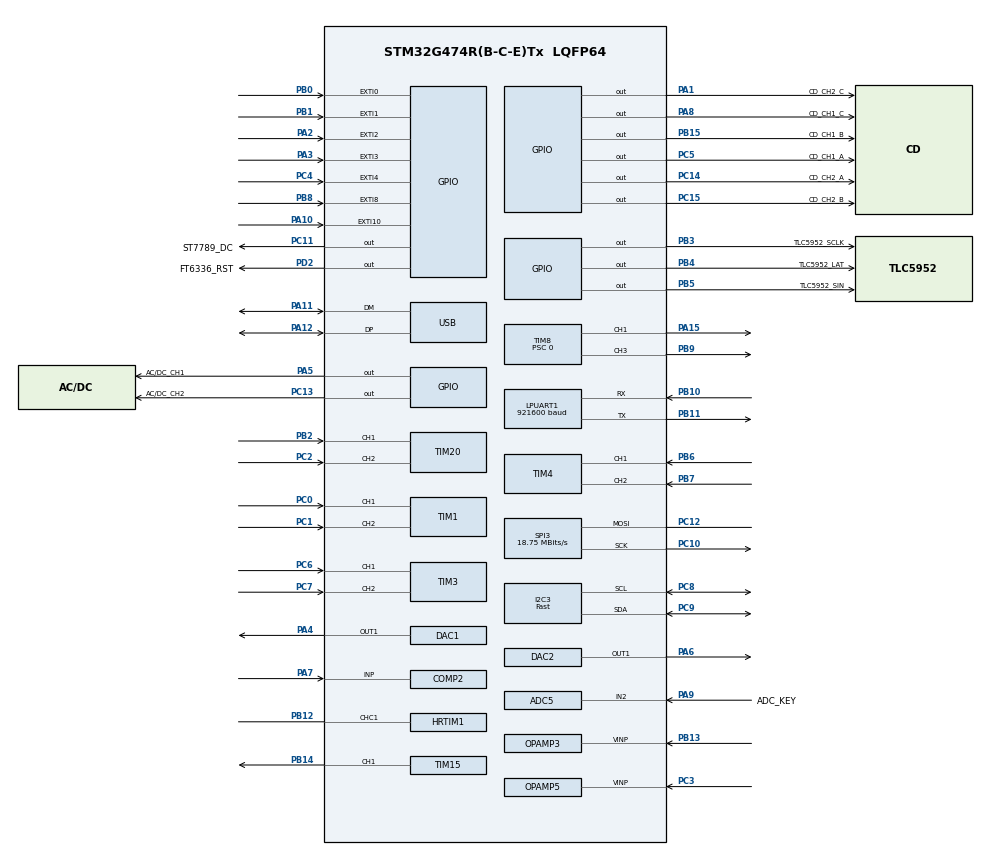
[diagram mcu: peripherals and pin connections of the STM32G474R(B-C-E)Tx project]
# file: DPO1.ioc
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ADC2.Channel-0\#ChannelRegularConversion=ADC_CHANNEL_4
ADC2.ClockPrescaler=ADC_CLOCK_ASYNC_DIV1
ADC2.ContinuousConvMode=DISABLE
ADC2.DMAContinuousRequests=ENABLE
ADC2.ExternalTrigConv=ADC_EXTERNALTRIG_T6_TRGO
ADC2.NbrOfConversionFlag=1
ADC2.OffsetNumber-0\#ChannelRegularConversion=ADC_OFFSET_NONE
ADC2.Overrun=ADC_OVR_DATA_OVERWRITTEN
ADC2.Rank-0\#ChannelRegularConversion=1
ADC2.SamplingTime-0\#ChannelRegularConversion=ADC_SAMPLETIME_2CYCLES_5
ADC3.Channel-0\#ChannelRegularConversion=ADC_CHANNEL_5
ADC3.ClockPrescaler=ADC_CLOCK_ASYNC_DIV1
ADC3.ContinuousConvMode=DISABLE
ADC3.DMAContinuousRequests=ENABLE
ADC3.ExternalTrigConv=ADC_EXTERNALTRIG_T6_TRGO
ADC3.NbrOfConversionFlag=1
ADC3.OffsetNumber-0\#ChannelRegularConversion=ADC_OFFSET_NONE
ADC3.Overrun=ADC_OVR_DATA_OVERWRITTEN
ADC3.Rank-0\#ChannelRegularConversion=1
ADC3.SamplingTime-0\#ChannelRegularConversion=ADC_SAMPLETIME_2CYCLES_5
ADC3.master=1
ADC5.AWD1FilteringConfig=ADC_AWD_FILTERING_NONE
ADC5.AWD1HighThreshold=4095
ADC5.AWD1ITMode=ENABLE
ADC5.AWD1LowThreshold=3500
ADC5.Channel-0\#ChannelRegularConversion=ADC_CHANNEL_2
ADC5.Channel-1\#ChannelRegularConversion=ADC_CHANNEL_TEMPSENSOR_ADC5
ADC5.Channel-2\#ChannelRegularConversion=ADC_CHANNEL_VBAT
ADC5.Channel-3\#ChannelRegularConversion=ADC_CHANNEL_VREFINT
ADC5.Channel-4\#ChannelRegularConversion=ADC_CHANNEL_VOPAMP5
ADC5.ClockPrescaler=ADC_CLOCK_ASYNC_DIV1
ADC5.ContinuousConvMode=ENABLE
ADC5.DMAContinuousRequests=ENABLE
ADC5.DiscontinuousConvMode=DISABLE
ADC5.EOCSelection=ADC_EOC_SEQ_CONV
ADC5.EnableAnalogWatchDog1=true
ADC5.ExternalTrigConv=ADC_EXTERNALTRIG_T7_TRGO
ADC5.NbrOfConversion=5
ADC5.NbrOfConversionFlag=1
ADC5.OffsetNumber-0\#ChannelRegularConversion=ADC_OFFSET_NONE
ADC5.OffsetNumber-1\#ChannelRegularConversion=ADC_OFFSET_NONE
ADC5.OffsetNumber-2\#ChannelRegularConversion=ADC_OFFSET_NONE
ADC5.OffsetNumber-3\#ChannelRegularConversion=ADC_OFFSET_NONE
ADC5.OffsetNumber-4\#ChannelRegularConversion=ADC_OFFSET_NONE
ADC5.Overrun=ADC_OVR_DATA_OVERWRITTEN
ADC5.Rank-0\#ChannelRegularConversion=1
ADC5.Rank-1\#ChannelRegularConversion=2
ADC5.Rank-2\#ChannelRegularConversion=3
ADC5.Rank-3\#ChannelRegularConversion=4
ADC5.Rank-4\#ChannelRegularConversion=5
ADC5.Resolution=ADC_RESOLUTION_12B
ADC5.SamplingTime-0\#ChannelRegularConversion=ADC_SAMPLETIME_640CYCLES_5
ADC5.SamplingTime-1\#ChannelRegularConversion=ADC_SAMPLETIME_640CYCLES_5
ADC5.SamplingTime-2\#ChannelRegularConversion=ADC_SAMPLETIME_640CYCLES_5
ADC5.SamplingTime-3\#ChannelRegularConversion=ADC_SAMPLETIME_640CYCLES_5
ADC5.SamplingTime-4\#ChannelRegularConversion=ADC_SAMPLETIME_640CYCLES_5
ADC5.WatchdogChannel=ADC_CHANNEL_2
ADC5.WatchdogMode=ADC_ANALOGWATCHDOG_SINGLE_REG
DAC1.DAC_Channel-DAC_OUT2_Int=DAC_CHANNEL_2
DAC1.DAC_Trigger2_OUT1-DAC_OUT1_ExtAndInt=DAC_TRIGGER_NONE
DAC1.DAC_Trigger_OUT1-DAC_OUT1_ExtAndInt=DAC_TRIGGER_SOFTWARE
DAC1.WaveGeneration_OUT1-DAC_OUT1_ExtAndInt=DISABLE
DAC2.DAC_Trigger_OUT1-DAC_OUT1_ExtAndInt=DAC_TRIGGER_SOFTWARE
DAC4.DAC_Trigger_OUT1-DAC_OUT1_Int=DAC_TRIGGER_SOFTWARE
Dma.ADC2.4.Direction=DMA_PERIPH_TO_MEMORY
Dma.ADC2.4.EventEnable=DISABLE
Dma.ADC2.4.Instance=DMA1_Channel5
Dma.ADC2.4.MemDataAlignment=DMA_MDATAALIGN_WORD
Dma.ADC2.4.MemInc=DMA_MINC_ENABLE
Dma.ADC2.4.Mode=DMA_CIRCULAR
Dma.ADC2.4.PeriphDataAlignment=DMA_PDATAALIGN_WORD
Dma.ADC2.4.PeriphInc=DMA_PINC_DISABLE
Dma.ADC2.4.Polarity=HAL_DMAMUX_REQ_GEN_RISING
Dma.ADC2.4.Priority=DMA_PRIORITY_LOW
Dma.ADC2.4.RequestNumber=1
Dma.ADC2.4.SignalID=NONE
Dma.ADC2.4.SyncEnable=DISABLE
Dma.ADC2.4.SyncPolarity=HAL_DMAMUX_SYNC_NO_EVENT
Dma.ADC2.4.SyncRequestNumber=1
Dma.ADC2.4.SyncSignalID=NONE
Dma.ADC3.5.Direction=DMA_PERIPH_TO_MEMORY
Dma.ADC3.5.EventEnable=DISABLE
Dma.ADC3.5.Instance=DMA1_Channel6
Dma.ADC3.5.MemDataAlignment=DMA_MDATAALIGN_WORD
Dma.ADC3.5.MemInc=DMA_MINC_ENABLE
Dma.ADC3.5.Mode=DMA_CIRCULAR
Dma.ADC3.5.PeriphDataAlignment=DMA_PDATAALIGN_WORD
Dma.ADC3.5.PeriphInc=DMA_PINC_DISABLE
Dma.ADC3.5.Polarity=HAL_DMAMUX_REQ_GEN_RISING
Dma.ADC3.5.Priority=DMA_PRIORITY_LOW
Dma.ADC3.5.RequestNumber=1
Dma.ADC3.5.SignalID=NONE
Dma.ADC3.5.SyncEnable=DISABLE
Dma.ADC3.5.SyncPolarity=HAL_DMAMUX_SYNC_NO_EVENT
Dma.ADC3.5.SyncRequestNumber=1
Dma.ADC3.5.SyncSignalID=NONE
Dma.ADC5.3.Direction=DMA_PERIPH_TO_MEMORY
Dma.ADC5.3.EventEnable=DISABLE
Dma.ADC5.3.Instance=DMA1_Channel4
Dma.ADC5.3.MemDataAlignment=DMA_MDATAALIGN_WORD
Dma.ADC5.3.MemInc=DMA_MINC_ENABLE
Dma.ADC5.3.Mode=DMA_CIRCULAR
Dma.ADC5.3.PeriphDataAlignment=DMA_PDATAALIGN_WORD
Dma.ADC5.3.PeriphInc=DMA_PINC_DISABLE
Dma.ADC5.3.Polarity=HAL_DMAMUX_REQ_GEN_RISING
Dma.ADC5.3.Priority=DMA_PRIORITY_LOW
Dma.ADC5.3.RequestNumber=1
Dma.ADC5.3.SignalID=NONE
Dma.ADC5.3.SyncEnable=DISABLE
Dma.ADC5.3.SyncPolarity=HAL_DMAMUX_SYNC_NO_EVENT
Dma.ADC5.3.SyncRequestNumber=1
Dma.ADC5.3.SyncSignalID=NONE
Dma.Request0=TIM8_CH3
Dma.Request1=TIM15_CH1
Dma.Request2=SPI3_TX
Dma.Request3=ADC5
Dma.Request4=ADC2
Dma.Request5=ADC3
Dma.SPI3_TX.2.Direction=DMA_MEMORY_TO_PERIPH
Dma.SPI3_TX.2.EventEnable=DISABLE
Dma.SPI3_TX.2.Instance=DMA1_Channel3
Dma.SPI3_TX.2.MemDataAlignment=DMA_MDATAALIGN_BYTE
Dma.SPI3_TX.2.MemInc=DMA_MINC_ENABLE
Dma.SPI3_TX.2.Mode=DMA_NORMAL
Dma.SPI3_TX.2.PeriphDataAlignment=DMA_PDATAALIGN_BYTE
Dma.SPI3_TX.2.PeriphInc=DMA_PINC_DISABLE
Dma.SPI3_TX.2.Polarity=HAL_DMAMUX_REQ_GEN_RISING
Dma.SPI3_TX.2.Priority=DMA_PRIORITY_LOW
Dma.SPI3_TX.2.RequestNumber=1
Dma.SPI3_TX.2.SignalID=NONE
Dma.SPI3_TX.2.SyncEnable=DISABLE
Dma.SPI3_TX.2.SyncPolarity=HAL_DMAMUX_SYNC_NO_EVENT
Dma.SPI3_TX.2.SyncRequestNumber=1
Dma.SPI3_TX.2.SyncSignalID=NONE
Dma.TIM15_CH1.1.Direction=DMA_MEMORY_TO_PERIPH
Dma.TIM15_CH1.1.EventEnable=DISABLE
Dma.TIM15_CH1.1.Instance=DMA1_Channel2
Dma.TIM15_CH1.1.MemDataAlignment=DMA_MDATAALIGN_HALFWORD
Dma.TIM15_CH1.1.MemInc=DMA_MINC_ENABLE
Dma.TIM15_CH1.1.Mode=DMA_NORMAL
Dma.TIM15_CH1.1.PeriphDataAlignment=DMA_PDATAALIGN_HALFWORD
Dma.TIM15_CH1.1.PeriphInc=DMA_PINC_DISABLE
Dma.TIM15_CH1.1.Polarity=HAL_DMAMUX_REQ_GEN_RISING
Dma.TIM15_CH1.1.Priority=DMA_PRIORITY_LOW
Dma.TIM15_CH1.1.RequestNumber=1
Dma.TIM15_CH1.1.SignalID=NONE
Dma.TIM15_CH1.1.SyncEnable=DISABLE
Dma.TIM15_CH1.1.SyncPolarity=HAL_DMAMUX_SYNC_NO_EVENT
Dma.TIM15_CH1.1.SyncRequestNumber=1
Dma.TIM15_CH1.1.SyncSignalID=NONE
Dma.TIM8_CH3.0.Direction=DMA_MEMORY_TO_PERIPH
Dma.TIM8_CH3.0.EventEnable=DISABLE
Dma.TIM8_CH3.0.Instance=DMA1_Channel1
Dma.TIM8_CH3.0.MemDataAlignment=DMA_MDATAALIGN_HALFWORD
Dma.TIM8_CH3.0.MemInc=DMA_MINC_ENABLE
Dma.TIM8_CH3.0.Mode=DMA_NORMAL
Dma.TIM8_CH3.0.PeriphDataAlignment=DMA_PDATAALIGN_HALFWORD
Dma.TIM8_CH3.0.PeriphInc=DMA_PINC_DISABLE
Dma.TIM8_CH3.0.Polarity=HAL_DMAMUX_REQ_GEN_RISING
Dma.TIM8_CH3.0.Priority=DMA_PRIORITY_LOW
Dma.TIM8_CH3.0.RequestNumber=1
Dma.TIM8_CH3.0.SignalID=NONE
Dma.TIM8_CH3.0.SyncEnable=DISABLE
Dma.TIM8_CH3.0.SyncPolarity=HAL_DMAMUX_SYNC_NO_EVENT
Dma.TIM8_CH3.0.SyncRequestNumber=1
Dma.TIM8_CH3.0.SyncSignalID=NONE
HRTIM1.CompareUnit1-Output_TC1=HRTIM_COMPAREUNIT_1
HRTIM1.CompareValue1-Output_TC1=48
HRTIM1.Configuration_TC=Waveform
HRTIM1.NumberResetSource1-Output_TC1=1
HRTIM1.NumberSetSource1-Output_TC1=1
HRTIM1.Periode_TC=96
HRTIM1.ResetOutput1_Source1-Output_TC1=HRTIM_OUTPUTRESET_TIMCMP1
HRTIM1.SetOutput1_Source1-Output_TC1=HRTIM_OUTPUTSET_TIMPER
I2C3.I2C_Speed_Mode=I2C_Fast
I2C3.Timing=0x10E32879
LPUART1.BaudRate=921600
Mcu.Family=STM32G4
Mcu.Name=STM32G474R(B-C-E)Tx
Mcu.Package=LQFP64
NVIC.ADC5_IRQn=true\:0\:0\:false\:false\:true\:true\:true\:true
NVIC.DMA1_Channel1_IRQn=true\:0\:0\:false\:false\:true\:false\:true\:true
NVIC.DMA1_Channel2_IRQn=true\:0\:0\:false\:false\:true\:false\:true\:true
NVIC.DMA1_Channel3_IRQn=true\:0\:0\:false\:false\:true\:false\:true\:true
NVIC.DMA1_Channel4_IRQn=true\:0\:0\:false\:false\:true\:false\:true\:true
NVIC.DMA1_Channel5_IRQn=true\:0\:0\:false\:false\:true\:false\:true\:true
NVIC.DMA1_Channel6_IRQn=true\:0\:0\:false\:false\:true\:false\:true\:true
NVIC.EXTI0_IRQn=true\:0\:0\:false\:false\:true\:true\:true\:true
NVIC.EXTI15_10_IRQn=true\:0\:0\:false\:false\:true\:true\:true\:true
NVIC.EXTI1_IRQn=true\:0\:0\:false\:false\:true\:true\:true\:true
NVIC.EXTI2_IRQn=true\:0\:0\:false\:false\:true\:true\:true\:true
NVIC.EXTI3_IRQn=true\:0\:0\:false\:false\:true\:true\:true\:true
NVIC.EXTI4_IRQn=true\:0\:0\:false\:false\:true\:true\:true\:true
NVIC.EXTI9_5_IRQn=true\:0\:0\:false\:false\:true\:true\:true\:true
NVIC.PriorityGroup=NVIC_PRIORITYGROUP_4
NVIC.USB_LP_IRQn=true\:0\:0\:false\:false\:true\:false\:true\:true
PA0.Signal=S_TIM2_ETR
PA1.GPIO_Label=CD_CH2_C
PA1.Signal=GPIO_Output
PA10.Signal=GPXTI10
PA11.Mode=Device
PA11.Signal=USB_DM
PA12.Mode=Device
PA12.Signal=USB_DP
PA13.Mode=Serial_Wire
PA13.Signal=SYS_JTMS-SWDIO
PA14.Mode=Serial_Wire
PA14.Signal=SYS_JTCK-SWCLK
PA15.GPIO_ModeDefaultPP=GPIO_MODE_AF_PP
PA15.GPIO_PuPd=GPIO_PULLDOWN
PA15.GPIO_Speed=GPIO_SPEED_FREQ_VERY_HIGH
PA15.Signal=S_TIM8_CH1
PA2.Signal=GPXTI2
PA3.Signal=GPXTI3
PA4.Signal=COMP_DAC11_group
PA5.GPIO_Label=AC/DC_CH1
PA5.Signal=GPIO_Output
PA6.Signal=COMP_DAC21_group
PA7.Signal=SharedAnalog_PA7
PA8.GPIO_Label=CD_CH1_C
PA8.Signal=GPIO_Output
PA9.GPIO_Label=ADC_KEY
PA9.Mode=IN2-Single-Ended
PA9.Signal=ADC5_IN2
PB0.Signal=GPXTI0
PB1.Signal=GPXTI1
PB10.Mode=Asynchronous
PB10.Signal=LPUART1_RX
PB11.Mode=Asynchronous
PB11.Signal=LPUART1_TX
PB12.Mode=Output_TC1
PB12.Signal=HRTIM1_CHC1
PB13.Signal=SharedAnalog_PB13
PB14.GPIO_ModeDefaultPP=GPIO_MODE_AF_PP
PB14.GPIO_PuPd=GPIO_PULLUP
PB14.GPIO_Speed=GPIO_SPEED_FREQ_VERY_HIGH
PB14.Signal=S_TIM15_CH1
PB15.GPIO_Label=CD_CH1_B
PB15.Signal=GPIO_Output
PB2.GPIO_PuPd=GPIO_PULLUP
PB2.GPIO_Speed=GPIO_SPEED_FREQ_VERY_HIGH
PB2.Signal=S_TIM20_CH1
PB3.GPIO_Label=TLC5952_SCLK
PB3.Signal=GPIO_Output
PB4.GPIO_Label=TLC5952_LAT
PB4.Signal=GPIO_Output
PB5.GPIO_Label=TLC5952_SIN
PB5.Signal=GPIO_Output
PB6.GPIO_PuPd=GPIO_PULLUP
PB6.GPIO_Speed=GPIO_SPEED_FREQ_VERY_HIGH
PB6.Signal=S_TIM4_CH1
PB7.GPIO_PuPd=GPIO_PULLUP
PB7.GPIO_Speed=GPIO_SPEED_FREQ_VERY_HIGH
PB7.Signal=S_TIM4_CH2
PB8-BOOT0.Signal=GPXTI8
PB9.GPIO_ModeDefaultPP=GPIO_MODE_AF_PP
PB9.GPIO_PuPd=GPIO_NOPULL
PB9.GPIO_Speed=GPIO_SPEED_FREQ_VERY_HIGH
PB9.Signal=S_TIM8_CH3
PC0.GPIO_PuPd=GPIO_PULLUP
PC0.GPIO_Speed=GPIO_SPEED_FREQ_VERY_HIGH
PC0.Signal=S_TIM1_CH1
PC1.GPIO_PuPd=GPIO_PULLUP
PC1.GPIO_Speed=GPIO_SPEED_FREQ_VERY_HIGH
PC1.Signal=S_TIM1_CH2
PC10.GPIO_Mode=GPIO_MODE_AF_PP
PC10.GPIO_PuPd=GPIO_NOPULL
PC10.GPIO_Speed=GPIO_SPEED_FREQ_VERY_HIGH
PC10.Mode=Simplex_Bidirectional_Master
PC10.Signal=SPI3_SCK
PC11.GPIO_Label=ST7789_DC
PC11.Signal=GPIO_Output
PC12.GPIO_Mode=GPIO_MODE_AF_PP
PC12.GPIO_PuPd=GPIO_NOPULL
PC12.GPIO_Speed=GPIO_SPEED_FREQ_VERY_HIGH
PC12.Mode=Simplex_Bidirectional_Master
PC12.Signal=SPI3_MOSI
PC13.GPIO_Label=AC/DC_CH2
PC13.Signal=GPIO_Output
PC14-OSC32_IN.GPIO_Label=CD_CH2_A
PC14-OSC32_IN.Signal=GPIO_Output
PC15-OSC32_OUT.GPIO_Label=CD_CH2_B
PC15-OSC32_OUT.Signal=GPIO_Output
PC2.GPIO_PuPd=GPIO_PULLUP
PC2.GPIO_Speed=GPIO_SPEED_FREQ_VERY_HIGH
PC2.Signal=S_TIM20_CH2
PC3.Mode=Follower_Internally_Connected
PC3.Signal=OPAMP5_VINP
PC4.Signal=GPXTI4
PC5.GPIO_Label=CD_CH1_A
PC5.Signal=GPIO_Output
PC6.GPIO_PuPd=GPIO_PULLUP
PC6.GPIO_Speed=GPIO_SPEED_FREQ_VERY_HIGH
PC6.Signal=S_TIM3_CH1
PC7.GPIO_PuPd=GPIO_PULLUP
PC7.GPIO_Speed=GPIO_SPEED_FREQ_VERY_HIGH
PC7.Signal=S_TIM3_CH2
PC8.Mode=I2C
PC8.Signal=I2C3_SCL
PC9.Mode=I2C
PC9.Signal=I2C3_SDA
PD2.GPIO_Label=FT6336_RST
PD2.Signal=GPIO_Output
PF0-OSC_IN.Mode=HSE-External-Oscillator
PF0-OSC_IN.Signal=RCC_OSC_IN
PF1-OSC_OUT.Mode=HSE-External-Oscillator
PF1-OSC_OUT.Signal=RCC_OSC_OUT
ProjectManager.HeapSize=0x200
ProjectManager.StackSize=0x400
ProjectManager.TargetToolchain=STM32CubeIDE
RCC.ADC12Freq_Value=150000000
RCC.ADC345CLockSelection=RCC_ADC345CLKSOURCE_PLL
RCC.ADC345Freq_Value=50000000
RCC.AHBFreq_Value=150000000
RCC.APB1Freq_Value=150000000
RCC.APB1TimFreq_Value=150000000
RCC.APB2Freq_Value=150000000
RCC.APB2TimFreq_Value=150000000
RCC.CK48CLockSelection=RCC_USBCLKSOURCE_HSI48
RCC.CortexFreq_Value=150000000
RCC.EXTERNAL_CLOCK_VALUE=12288000
RCC.EnbaleCSS=true
RCC.HCLKFreq_Value=150000000
RCC.HSE_VALUE=8000000
RCC.HSI48_VALUE=48000000
RCC.HSI_VALUE=16000000
RCC.LSE_VALUE=32768
RCC.PLLM=RCC_PLLM_DIV2
RCC.PLLN=75
RCC.PLLP=RCC_PLLP_DIV6
RCC.PLLSourceVirtual=RCC_PLLSOURCE_HSE
RCC.SYSCLKFreq_VALUE=150000000
RCC.SYSCLKSource=RCC_SYSCLKSOURCE_PLLCLK
RCC.USBFreq_Value=48000000
RCC.VCOOutputFreq_Value=300000000
SH.COMP_DAC11_group.0=DAC1_OUT1,DAC_OUT1_ExtAndInt
SH.COMP_DAC21_group.0=DAC2_OUT1,DAC_OUT1_ExtAndInt
SH.S_TIM15_CH1.0=TIM15_CH1,PWM Generation1 CH1
SH.S_TIM1_CH1.0=TIM1_CH1,Encoder_Interface
SH.S_TIM1_CH2.0=TIM1_CH2,Encoder_Interface
SH.S_TIM20_CH1.0=TIM20_CH1,Encoder_Interface
SH.S_TIM20_CH2.0=TIM20_CH2,Encoder_Interface
SH.S_TIM2_ETR.0=TIM2_ETR
SH.S_TIM3_CH1.0=TIM3_CH1,Encoder_Interface
SH.S_TIM3_CH2.0=TIM3_CH2,Encoder_Interface
SH.S_TIM4_CH1.0=TIM4_CH1,Encoder_Interface
SH.S_TIM4_CH2.0=TIM4_CH2,Encoder_Interface
SH.S_TIM8_CH1.0=TIM8_CH1,PWM Generation1 CH1
SH.S_TIM8_CH3.0=TIM8_CH3,PWM Generation3 CH3
SH.SharedAnalog_PA7.0=COMP2_INP,INP
SH.SharedAnalog_PA7.1=OPAMP1_VINP,PGA_Internally_Connected
SH.SharedAnalog_PA7.2=OPAMP2_VINP,Follower_Internally_Connected
SH.SharedAnalog_PA7.3=ADC2_IN4,IN4-Single-Ended
SH.SharedAnalog_PB13.0=OPAMP3_VINP,Follower_Internally_Connected
SH.SharedAnalog_PB13.1=COMP5_INP,INP
SH.SharedAnalog_PB13.2=OPAMP6_VINP,PGA_Internally_Connected
SH.SharedAnalog_PB13.3=ADC3_IN5,IN5-Single-Ended
SPI3.BaudRatePrescaler=SPI_BAUDRATEPRESCALER_8
SPI3.CLKPolarity=SPI_POLARITY_HIGH
SPI3.CalculateBaudRate=18.75 MBits/s
SPI3.DataSize=SPI_DATASIZE_8BIT
SPI3.Direction=SPI_DIRECTION_1LINE
SPI3.Mode=SPI_MODE_MASTER
SPI3.VirtualType=VM_MASTER
STMicroelectronics.X-CUBE-TOUCHGFX.4.25.0.tgfx_block_size=9600
STMicroelectronics.X-CUBE-TOUCHGFX.4.25.0.tgfx_buffering_strategy=Partial
STMicroelectronics.X-CUBE-TOUCHGFX.4.25.0.tgfx_custom_height=240
STMicroelectronics.X-CUBE-TOUCHGFX.4.25.0.tgfx_custom_width=320
STMicroelectronics.X-CUBE-TOUCHGFX.4.25.0.tgfx_datareader=Disabled
STMicroelectronics.X-CUBE-TOUCHGFX.4.25.0_IsPackSelfContextualization=true
TIM1.IC1Filter=15
TIM1.IC2Filter=15
TIM15.Channel-PWM\ Generation1\ CH1=TIM_CHANNEL_1
TIM15.OCMode_PWM-PWM\ Generation1\ CH1=TIM_OCMODE_PWM1
TIM15.PeriodNoDither=1000-1
TIM15.Prescaler=150
TIM15.PulseNoDither_1=500-1
TIM20.IC1Filter=15
TIM20.IC2Filter=15
TIM3.EncoderMode=TIM_ENCODERMODE_TI1
TIM3.IC1Filter=15
TIM3.IC2Filter=15
TIM4.EncoderMode=TIM_ENCODERMODE_TI1
TIM4.IC1Filter=15
TIM4.IC2Filter=15
TIM6.PeriodNoDither=45-1
TIM6.TIM_MasterOutputTrigger=TIM_TRGO_UPDATE
TIM7.PeriodNoDither=10000-1
TIM7.Prescaler=180-1
TIM7.TIM_MasterOutputTrigger=TIM_TRGO_UPDATE
TIM8.Channel-PWM\ Generation1\ CH1=TIM_CHANNEL_1
TIM8.Channel-PWM\ Generation3\ CH3=TIM_CHANNEL_3
TIM8.ClockDivision=TIM_CLOCKDIVISION_DIV1
TIM8.Dithering=Disable
TIM8.OC1Preload_PWM=ENABLE
TIM8.OC3Preload_PWM=ENABLE
TIM8.OCIdleState_3=TIM_OCIDLESTATE_SET
TIM8.OCMode_PWM-PWM\ Generation1\ CH1=TIM_OCMODE_PWM2
TIM8.OCMode_PWM-PWM\ Generation3\ CH3=TIM_OCMODE_PWM1
TIM8.OCPolarity_1=TIM_OCPOLARITY_LOW
TIM8.OCPolarity_3=TIM_OCPOLARITY_HIGH
TIM8.PeriodNoDither=180-1
TIM8.Prescaler=0
TIM8.PulseNoDither_1=90
TIM8.PulseNoDither_3=90
USB_DEVICE.APP_RX_DATA_SIZE=1024
USB_DEVICE.APP_TX_DATA_SIZE=1024
USB_DEVICE.CLASS_NAME_FS=CDC
USB_DEVICE.VirtualMode=Cdc
USB_DEVICE.VirtualModeFS=Cdc_FS
VP_ADC5_OPAMP_INTERNAL5.Mode=IN-OPAMP5
VP_ADC5_TempSens_Input.Mode=IN-TempSens
VP_ADC5_Vbat_Input.Mode=IN-Vbat
VP_ADC5_Vref_Input.Mode=IN-Vrefint
VP_COMP2_VS_DAC1OUT2.Mode=INM_DAC1OUT2
VP_COMP5_VS_DAC1OUT2.Mode=INM_DAC1OUT2
VP_CRC_VS_CRC.Mode=CRC_Activate
VP_DAC1_VS_DACI2.Mode=DAC_OUT2_Int
VP_DAC4_VS_DACI1.Mode=DAC_OUT1_Int
VP_SYS_VS_DBSignals.Mode=DisableDeadBatterySignals
VP_SYS_V_VREFBUF.Mode=ExternalMode
VP_TIM15_VS_ClockSourceINT.Mode=Internal
VP_TIM6_VS_ClockSourceINT.Mode=Enable_Timer
VP_TIM7_VS_ClockSourceINT.Mode=Enable_Timer
VP_TIM8_VS_ClockSourceINT.Mode=Internal
VP_USB_DEVICE_VS_USB_DEVICE_CDC_FS.Mode=CDC_FS
board=custom

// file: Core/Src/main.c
/* USER CODE BEGIN Header */
/**
  ******************************************************************************
  * @file           : main.c
  * @brief          : Main program body
  ******************************************************************************
  * @attention
  *
  * Copyright (c) 2025 STMicroelectronics.
  * All rights reserved.
  *
  * This software is licensed under terms that can be found in the LICENSE file
  * in the root directory of this software component.
  * If no LICENSE file comes with this software, it is provided AS-IS.
  *
  ******************************************************************************
  */
/* USER CODE END Header */
#include "main.h"
#include "usb_device.h"

/* USER CODE BEGIN Includes */

#include "usbd_cdc_if.h"

#include "MyLib.h"

#include "ft6336.h"

#include "st7789.h"

#include "TLC5952.h"

#include "ws2812.h"

#include "Views.h"

/* USER CODE END Includes */

ADC_HandleTypeDef hadc2;
ADC_HandleTypeDef hadc3;
ADC_HandleTypeDef hadc5;
DMA_HandleTypeDef hdma_adc2;
DMA_HandleTypeDef hdma_adc3;
DMA_HandleTypeDef hdma_adc5;

COMP_HandleTypeDef hcomp2;
COMP_HandleTypeDef hcomp5;

CRC_HandleTypeDef hcrc;

DAC_HandleTypeDef hdac1;
DAC_HandleTypeDef hdac2;
DAC_HandleTypeDef hdac4;

HRTIM_HandleTypeDef hhrtim1;

I2C_HandleTypeDef hi2c3;

UART_HandleTypeDef hlpuart1;

OPAMP_HandleTypeDef hopamp1;
OPAMP_HandleTypeDef hopamp2;
OPAMP_HandleTypeDef hopamp3;
OPAMP_HandleTypeDef hopamp5;
OPAMP_HandleTypeDef hopamp6;

SPI_HandleTypeDef hspi3;
DMA_HandleTypeDef hdma_spi3_tx;

TIM_HandleTypeDef htim1;
TIM_HandleTypeDef htim3;
TIM_HandleTypeDef htim4;
TIM_HandleTypeDef htim6;
TIM_HandleTypeDef htim7;
TIM_HandleTypeDef htim8;
TIM_HandleTypeDef htim15;
TIM_HandleTypeDef htim20;
DMA_HandleTypeDef hdma_tim8_ch3;
DMA_HandleTypeDef hdma_tim15_ch1;

void SystemClock_Config(void);
static void MX_GPIO_Init(void);
static void MX_DMA_Init(void);
static void MX_COMP2_Init(void);
static void MX_COMP5_Init(void);
static void MX_DAC1_Init(void);
static void MX_DAC2_Init(void);
static void MX_OPAMP1_Init(void);
static void MX_OPAMP2_Init(void);
static void MX_OPAMP3_Init(void);
static void MX_OPAMP6_Init(void);
static void MX_TIM1_Init(void);
static void MX_TIM4_Init(void);
static void MX_TIM20_Init(void);
static void MX_TIM3_Init(void);
static void MX_ADC5_Init(void);
static void MX_TIM15_Init(void);
static void MX_TIM8_Init(void);
static void MX_SPI3_Init(void);
static void MX_I2C3_Init(void);
static void MX_DAC4_Init(void);
static void MX_LPUART1_UART_Init(void);
static void MX_OPAMP5_Init(void);
static void MX_TIM7_Init(void);
static void MX_ADC2_Init(void);
static void MX_ADC3_Init(void);
static void MX_TIM6_Init(void);
static void MX_HRTIM1_Init(void);
static void MX_CRC_Init(void);

/* USER CODE BEGIN 0 */

#define DPO_DEEP 4096
#define DPO_DEEP_HALF DPO_DEEP/2

unsigned char BUFFER_CDC[500]={"abcd\r\n"};

uint32_t BUFFER_SYS_ADC[5]={0};
uint32_t BUFFER_DPO_CH1[DPO_DEEP]={0};
uint32_t BUFFER_DPO_CH2[DPO_DEEP]={0};

uint32_t BUFFER_DPO_CH1_PROC[DPO_DEEP]={0};
uint32_t BUFFER_DPO_CH2_PROC[DPO_DEEP]={0};

uint16_t DDS_Onboard_Period = 96;
uint16_t DDS_Onboard_COMPAREUNIT = 48;

uint32_t color = 0x000000;

uint64_t DEBUG_COUNT = 0;

uint16_t prev_cnt1 = 32767;
uint16_t prev_cnt3 = 32767;
uint16_t prev_cnt4 = 32767;
uint16_t prev_cnt20 = 32767;

Input_HandleTypeDef input={0};

// 彩虹颜色配置
RGBColor rainbow_colors[WS2812_NUM] = {
    {255,   0,   0},
    {255, 115,   0},
    {255, 201,   0},
    {229, 242,   0},
    { 51, 153,   0},
    {  0,  64, 127},
    { 14,   0, 230},
    { 67,   0, 142},
    {172,  77, 194},
    {243,  91, 166}
};

// DMA发送配置
RGBColor WS2812_colors[WS2812_NUM] = {
    {255,   0,   0},
    {255, 115,   0},
    {255, 201,   0},
    {229, 242,   0},
    { 51, 153,   0},
    {  0,  64, 127},
    { 14,   0, 230},
    { 67,   0, 142},
    {172,  77, 194},
    {243,  91, 166}
};

//memcpy(WS2812_colors, rainbow_colors, sizeof(rainbow_colors));

FEAnalogStates FEAnalog = {
    .AC_DC_CH1 = GPIO_PIN_RESET,
    .AC_DC_CH2 = GPIO_PIN_RESET,
    .CD_CH1 = 0,
    .CD_CH2 = 0,
    .OFFSET1 = 2200,
    .OFFSET2 = 2200
};

void Analog_FE_Update(void) {
	HAL_GPIO_WritePin(AC_DC_CH1_GPIO_Port, AC_DC_CH1_Pin, (GPIO_PinState)FEAnalog.AC_DC_CH1);

	HAL_GPIO_WritePin(CD_CH1_A_GPIO_Port, CD_CH1_A_Pin, (GPIO_PinState)((FEAnalog.CD_CH1 >> 1) & 0x01));
	HAL_GPIO_WritePin(CD_CH1_B_GPIO_Port, CD_CH1_B_Pin, (GPIO_PinState)((FEAnalog.CD_CH1 >> 2) & 0x01));
	HAL_GPIO_WritePin(CD_CH1_C_GPIO_Port, CD_CH1_C_Pin, (GPIO_PinState)((FEAnalog.CD_CH1 >> 3) & 0x01));

	HAL_GPIO_WritePin(AC_DC_CH2_GPIO_Port, AC_DC_CH2_Pin, (GPIO_PinState)FEAnalog.AC_DC_CH2);

	HAL_GPIO_WritePin(CD_CH2_A_GPIO_Port, CD_CH2_A_Pin, (GPIO_PinState)((FEAnalog.CD_CH2 >> 1) & 0x01));
	HAL_GPIO_WritePin(CD_CH2_B_GPIO_Port, CD_CH2_B_Pin, (GPIO_PinState)((FEAnalog.CD_CH2 >> 2) & 0x01));
	HAL_GPIO_WritePin(CD_CH2_C_GPIO_Port, CD_CH2_C_Pin, (GPIO_PinState)((FEAnalog.CD_CH2 >> 3) & 0x01));

	//SET OFFSET
	HAL_DAC_SetValue(&hdac2, DAC_CHANNEL_1, DAC_ALIGN_12B_R, FEAnalog.OFFSET1);
	HAL_DAC_SetValue(&hdac1, DAC_CHANNEL_1, DAC_ALIGN_12B_R, FEAnalog.OFFSET2);
	HAL_DAC_Start(&hdac2, DAC_CHANNEL_1);
	HAL_DAC_Start(&hdac1, DAC_CHANNEL_1);
}

void DDS_Onboard_Update(void) {
__HAL_HRTIM_SETPERIOD(&hhrtim1, HRTIM_TIMERINDEX_TIMER_C, DDS_Onboard_Period);
__HAL_HRTIM_SETCOMPARE(&hhrtim1, HRTIM_TIMERINDEX_TIMER_C , HRTIM_COMPAREUNIT_1, DDS_Onboard_COMPAREUNIT);
}

// 编码器处理函数
void KEY_PROCESS(void) {
	    // 处理按键
	    if (input.KEY0) {
	        printf("KEY0 is pressed.\n");
	    }
	    if (input.KEY1) {
	        printf("KEY1 is pressed.\n");
	    }
	    if (input.KEY2) {
	        printf("KEY2 is pressed.\n");
	    }
	    if (input.KEY3) {
	        printf("KEY3 is pressed.\n");
	    }
	    if (input.KEY4) {
	        printf("KEY4 is pressed.\n");
	    }
	    if (input.KEY5) {
	        printf("KEY5 is pressed.\n");
	    }
	    if (input.KEY_ENC0) {
	        printf("KEY_ENC0 is pressed.\n");
	    }
	    if (input.KEY_ENC1) {
	        printf("KEY_ENC1 is pressed.\n");
	    }
	    if (input.KEY_ENC2) {
	        printf("KEY_ENC2 is pressed.\n");
	    }
	    if (input.KEY_ENC3) {
	        printf("KEY_ENC3 is pressed.\n");
	    }

	    // 处理触摸坐标
	    if (input.Touched) {
	        printf("Touch detected at coordinates (%u, %u).\n", input.touch_x, input.touch_y);
	    }

	    memset(&input, 0, sizeof(Input_HandleTypeDef));
}

// 用于累加差值的临时变量
int32_t accumulated_diff1 = 0;
int32_t accumulated_diff2 = 0;
int32_t accumulated_diff3 = 0;
int32_t accumulated_diff4 = 0;

uint8_t CH_selected=0;
uint8_t LOCK_CH1=0;
uint8_t LOCK_CH2=0;

// 编码器处理函数
void ENC_PROCESS(void) {
	int32_t diff;
	uint32_t current_cnt;

	if (CH_selected) {
	current_cnt = htim4.Instance->CNT;
	htim4.Instance->CNT=32767;
	diff = (int32_t)(current_cnt - 32767)*((FEAnalog.CD_CH2+1));
	handle_overflow(&FEAnalog.OFFSET1, diff, 0, 4095);

	current_cnt = htim3.Instance->CNT;
	htim3.Instance->CNT=32767;
	diff = (int32_t)(current_cnt - 32767);
	handle_overflow(&FEAnalog.CD_CH1, -diff, 0, 14);
	}
	else
	{
	current_cnt = htim4.Instance->CNT;
	htim4.Instance->CNT=32767;
	diff = (int32_t)(current_cnt - 32767)*((FEAnalog.CD_CH2+1));
	handle_overflow(&FEAnalog.OFFSET2, diff, 0, 4095);

	current_cnt = htim3.Instance->CNT;
	htim3.Instance->CNT=32767;
	diff = (int32_t)(current_cnt - 32767);
	handle_overflow(&FEAnalog.CD_CH2, -diff, 0, 14);
	}

	current_cnt = htim20.Instance->CNT;
	htim20.Instance->CNT=32767;
	diff = (int32_t)(32767 - current_cnt);
	handle_overflow(&htim8.Instance->CCR1, diff, 4, 180);

	current_cnt = htim1.Instance->CNT;
	htim1.Instance->CNT=32767;
	diff = (int32_t)(current_cnt - 32767);
	handle_overflow(&WS2812_Brightness, diff, 0, 255);
	WS2812_Write_Colors(rainbow_colors, 10);

}

/* USER CODE END 0 */

int main(void)
{

  /* MCU Configuration--------------------------------------------------------*/

  /* Reset of all peripherals, Initializes the Flash interface and the Systick. */
  HAL_Init();

  /* Configure the system clock */
  SystemClock_Config();

  /* Initialize all configured peripherals */
  MX_GPIO_Init();
  MX_DMA_Init();
  MX_USB_Device_Init();
  MX_COMP2_Init();
  MX_COMP5_Init();
  MX_DAC1_Init();
  MX_DAC2_Init();
  MX_OPAMP1_Init();
  MX_OPAMP2_Init();
  MX_OPAMP3_Init();
  MX_OPAMP6_Init();
  MX_TIM1_Init();
  MX_TIM4_Init();
  MX_TIM20_Init();
  MX_TIM3_Init();
  MX_ADC5_Init();
  MX_TIM15_Init();
  MX_TIM8_Init();
  MX_SPI3_Init();
  MX_I2C3_Init();
  MX_DAC4_Init();
  MX_LPUART1_UART_Init();
  MX_OPAMP5_Init();
  MX_TIM7_Init();
  MX_ADC2_Init();
  MX_ADC3_Init();
  MX_TIM6_Init();
  MX_HRTIM1_Init();
  MX_CRC_Init();
  /* USER CODE BEGIN 2 */

  htim1.Instance->CNT=32767;
  htim3.Instance->CNT=32767;
  htim4.Instance->CNT=32767;
  htim20.Instance->CNT=32767;

//
//
//  HAL_OPAMP_Start(&hopamp1);
//  HAL_OPAMP_Start(&hopamp2);
//  HAL_OPAMP_Start(&hopamp3);
//  HAL_OPAMP_Start(&hopamp4);
//  HAL_OPAMP_Start(&hopamp5);
//  HAL_OPAMP_Start(&hopamp6);

	HAL_ADC_Start_DMA(&hadc2, BUFFER_DPO_CH2, DPO_DEEP);
	HAL_ADC_Start_DMA(&hadc3, BUFFER_DPO_CH1, DPO_DEEP);

  HAL_ADC_Start_DMA(&hadc5, BUFFER_SYS_ADC, 5);
  HAL_TIM_Base_Start(&htim6);
  HAL_TIM_Base_Start(&htim7);

  HAL_TIM_Encoder_Start(&htim1, TIM_CHANNEL_ALL);
  HAL_TIM_Encoder_Start(&htim3, TIM_CHANNEL_ALL);
  HAL_TIM_Encoder_Start(&htim4, TIM_CHANNEL_ALL);
  HAL_TIM_Encoder_Start(&htim20, TIM_CHANNEL_ALL);

  HAL_TIM_PWM_Start(&htim15, TIM_CHANNEL_1);
  HAL_TIM_PWM_Start(&htim8, TIM_CHANNEL_1);

  FT6336_Init();
  ST7789_Init();

  View_DoubaoWelcome();

  HAL_HRTIM_WaveformOutputStart(&hhrtim1, HRTIM_OUTPUT_TC1);  // Enable the generation of the waveform signal on the designated output
  HAL_HRTIM_WaveformCounterStart(&hhrtim1, HRTIM_TIMERID_TIMER_C);  // Start the counter of the Timer A operating in waveform mode

//  HAL_DAC_SetValue(&hdac4, DAC_CHANNEL_1, DAC_ALIGN_12B_R, 2048);
//HAL_DAC_Start(&hdac4, DAC_CHANNEL_1);

  /* USER CODE END 2 */

  /* Infinite loop */
  /* USER CODE BEGIN WHILE */
  while (1)
  {
	ENC_PROCESS();
	KEY_PROCESS();
//	  ST7789_Test();
//	  ST7789_WriteString(10, 10, " !\"#\%\$", Han_Array, WHITE, BLACK);

	WS2812_Write_Colors(WS2812_colors, 10);

	Analog_FE_Update();

	View_Config();

	while(LOCK_CH1){
		for (int i = 0; i < DPO_DEEP; i++) {
			sprintf(BUFFER_CDC,"ADC: %d,%d \r\n", BUFFER_DPO_CH1_PROC[i],BUFFER_DPO_CH2_PROC[i]);

	    	CDC_Transmit_FS(BUFFER_CDC, strlen(BUFFER_CDC));

//			printf("ADC: %d,%d \r\n", BUFFER_DPO_CH1_PROC[i],BUFFER_DPO_CH2_PROC[i]);

		}
		LOCK_CH1=0;
	}

	TLC5952_WriteLED();
	TLC5952_WriteControl();

//	  HAL_ADC_Start(&hadc5);
//	  result = HAL_ADC_GetValue(&hadc5);
//
//	  sprintf(BUFFER_CDC, "Result: %d \r\n", result);
//
//	  HAL_Delay(100);
//	  CDC_Transmit_FS(BUFFER_CDC, strlen(BUFFER_CDC));
    /* USER CODE END WHILE */

  }
}

void SystemClock_Config(void)
{
  RCC_OscInitTypeDef RCC_OscInitStruct = {0};
  RCC_ClkInitTypeDef RCC_ClkInitStruct = {0};

  /** Configure the main internal regulator output voltage
  */
  HAL_PWREx_ControlVoltageScaling(PWR_REGULATOR_VOLTAGE_SCALE1);

  /** Initializes the RCC Oscillators according to the specified parameters
  * in the RCC_OscInitTypeDef structure.
  */
  RCC_OscInitStruct.OscillatorType = RCC_OSCILLATORTYPE_HSI48|RCC_OSCILLATORTYPE_HSE;
  RCC_OscInitStruct.HSEState = RCC_HSE_ON;
  RCC_OscInitStruct.HSI48State = RCC_HSI48_ON;
  RCC_OscInitStruct.PLL.PLLState = RCC_PLL_ON;
  RCC_OscInitStruct.PLL.PLLSource = RCC_PLLSOURCE_HSE;
  RCC_OscInitStruct.PLL.PLLM = RCC_PLLM_DIV2;
  RCC_OscInitStruct.PLL.PLLN = 90;
  RCC_OscInitStruct.PLL.PLLP = RCC_PLLP_DIV6;
  RCC_OscInitStruct.PLL.PLLQ = RCC_PLLQ_DIV2;
  RCC_OscInitStruct.PLL.PLLR = RCC_PLLR_DIV2;
  if (HAL_RCC_OscConfig(&RCC_OscInitStruct) != HAL_OK)
  {
    Error_Handler();
  }

  /** Initializes the CPU, AHB and APB buses clocks
  */
  RCC_ClkInitStruct.ClockType = RCC_CLOCKTYPE_HCLK|RCC_CLOCKTYPE_SYSCLK
                              |RCC_CLOCKTYPE_PCLK1|RCC_CLOCKTYPE_PCLK2;
  RCC_ClkInitStruct.SYSCLKSource = RCC_SYSCLKSOURCE_PLLCLK;
  RCC_ClkInitStruct.AHBCLKDivider = RCC_SYSCLK_DIV1;
  RCC_ClkInitStruct.APB1CLKDivider = RCC_HCLK_DIV1;
  RCC_ClkInitStruct.APB2CLKDivider = RCC_HCLK_DIV1;

  if (HAL_RCC_ClockConfig(&RCC_ClkInitStruct, FLASH_LATENCY_4) != HAL_OK)
  {
    Error_Handler();
  }

  /** Enables the Clock Security System
  */
  HAL_RCC_EnableCSS();
}

static void MX_ADC2_Init(void)
{

  ADC_ChannelConfTypeDef sConfig = {0};

  /** Common config
  */
  hadc2.Instance = ADC2;
  hadc2.Init.ClockPrescaler = ADC_CLOCK_ASYNC_DIV1;
  hadc2.Init.Resolution = ADC_RESOLUTION_12B;
  hadc2.Init.DataAlign = ADC_DATAALIGN_RIGHT;
  hadc2.Init.GainCompensation = 0;
  hadc2.Init.ScanConvMode = ADC_SCAN_DISABLE;
  hadc2.Init.EOCSelection = ADC_EOC_SINGLE_CONV;
  hadc2.Init.LowPowerAutoWait = DISABLE;
  hadc2.Init.ContinuousConvMode = DISABLE;
  hadc2.Init.NbrOfConversion = 1;
  hadc2.Init.DiscontinuousConvMode = DISABLE;
  hadc2.Init.ExternalTrigConv = ADC_EXTERNALTRIG_T6_TRGO;
  hadc2.Init.ExternalTrigConvEdge = ADC_EXTERNALTRIGCONVEDGE_RISING;
  hadc2.Init.DMAContinuousRequests = ENABLE;
  hadc2.Init.Overrun = ADC_OVR_DATA_OVERWRITTEN;
  hadc2.Init.OversamplingMode = DISABLE;
  if (HAL_ADC_Init(&hadc2) != HAL_OK)
  {
    Error_Handler();
  }

  /** Configure Regular Channel
  */
  sConfig.Channel = ADC_CHANNEL_4;
  sConfig.Rank = ADC_REGULAR_RANK_1;
  sConfig.SamplingTime = ADC_SAMPLETIME_2CYCLES_5;
  sConfig.SingleDiff = ADC_SINGLE_ENDED;
  sConfig.OffsetNumber = ADC_OFFSET_NONE;
  sConfig.Offset = 0;
  if (HAL_ADC_ConfigChannel(&hadc2, &sConfig) != HAL_OK)
  {
    Error_Handler();
  }

}

static void MX_ADC3_Init(void)
{

  ADC_MultiModeTypeDef multimode = {0};
  ADC_ChannelConfTypeDef sConfig = {0};

  /** Common config
  */
  hadc3.Instance = ADC3;
  hadc3.Init.ClockPrescaler = ADC_CLOCK_ASYNC_DIV1;
  hadc3.Init.Resolution = ADC_RESOLUTION_12B;
  hadc3.Init.DataAlign = ADC_DATAALIGN_RIGHT;
  hadc3.Init.GainCompensation = 0;
  hadc3.Init.ScanConvMode = ADC_SCAN_DISABLE;
  hadc3.Init.EOCSelection = ADC_EOC_SINGLE_CONV;
  hadc3.Init.LowPowerAutoWait = DISABLE;
  hadc3.Init.ContinuousConvMode = DISABLE;
  hadc3.Init.NbrOfConversion = 1;
  hadc3.Init.DiscontinuousConvMode = DISABLE;
  hadc3.Init.ExternalTrigConv = ADC_EXTERNALTRIG_T6_TRGO;
  hadc3.Init.ExternalTrigConvEdge = ADC_EXTERNALTRIGCONVEDGE_RISING;
  hadc3.Init.DMAContinuousRequests = ENABLE;
  hadc3.Init.Overrun = ADC_OVR_DATA_OVERWRITTEN;
  hadc3.Init.OversamplingMode = DISABLE;
  if (HAL_ADC_Init(&hadc3) != HAL_OK)
  {
    Error_Handler();
  }

  /** Configure the ADC multi-mode
  */
  multimode.Mode = ADC_MODE_INDEPENDENT;
  if (HAL_ADCEx_MultiModeConfigChannel(&hadc3, &multimode) != HAL_OK)
  {
    Error_Handler();
  }

  /** Configure Regular Channel
  */
  sConfig.Channel = ADC_CHANNEL_5;
  sConfig.Rank = ADC_REGULAR_RANK_1;
  sConfig.SamplingTime = ADC_SAMPLETIME_2CYCLES_5;
  sConfig.SingleDiff = ADC_SINGLE_ENDED;
  sConfig.OffsetNumber = ADC_OFFSET_NONE;
  sConfig.Offset = 0;
  if (HAL_ADC_ConfigChannel(&hadc3, &sConfig) != HAL_OK)
  {
    Error_Handler();
  }

}

static void MX_ADC5_Init(void)
{

  ADC_AnalogWDGConfTypeDef AnalogWDGConfig = {0};
  ADC_ChannelConfTypeDef sConfig = {0};

  /** Common config
  */
  hadc5.Instance = ADC5;
  hadc5.Init.ClockPrescaler = ADC_CLOCK_ASYNC_DIV1;
  hadc5.Init.Resolution = ADC_RESOLUTION_12B;
  hadc5.Init.DataAlign = ADC_DATAALIGN_RIGHT;
  hadc5.Init.GainCompensation = 0;
  hadc5.Init.ScanConvMode = ADC_SCAN_ENABLE;
  hadc5.Init.EOCSelection = ADC_EOC_SEQ_CONV;
  hadc5.Init.LowPowerAutoWait = DISABLE;
  hadc5.Init.ContinuousConvMode = ENABLE;
  hadc5.Init.NbrOfConversion = 5;
  hadc5.Init.DiscontinuousConvMode = DISABLE;
  hadc5.Init.ExternalTrigConv = ADC_EXTERNALTRIG_T7_TRGO;
  hadc5.Init.ExternalTrigConvEdge = ADC_EXTERNALTRIGCONVEDGE_RISING;
  hadc5.Init.DMAContinuousRequests = ENABLE;
  hadc5.Init.Overrun = ADC_OVR_DATA_OVERWRITTEN;
  hadc5.Init.OversamplingMode = DISABLE;
  if (HAL_ADC_Init(&hadc5) != HAL_OK)
  {
    Error_Handler();
  }

  /** Configure Analog WatchDog 1
  */
  AnalogWDGConfig.WatchdogNumber = ADC_ANALOGWATCHDOG_1;
  AnalogWDGConfig.WatchdogMode = ADC_ANALOGWATCHDOG_SINGLE_REG;
  AnalogWDGConfig.Channel = ADC_CHANNEL_2;
  AnalogWDGConfig.ITMode = ENABLE;
  AnalogWDGConfig.HighThreshold = 4095;
  AnalogWDGConfig.LowThreshold = 3500;
  AnalogWDGConfig.FilteringConfig = ADC_AWD_FILTERING_NONE;
  if (HAL_ADC_AnalogWDGConfig(&hadc5, &AnalogWDGConfig) != HAL_OK)
  {
    Error_Handler();
  }

  /** Configure Regular Channel
  */
  sConfig.Channel = ADC_CHANNEL_2;
  sConfig.Rank = ADC_REGULAR_RANK_1;
  sConfig.SamplingTime = ADC_SAMPLETIME_640CYCLES_5;
  sConfig.SingleDiff = ADC_SINGLE_ENDED;
  sConfig.OffsetNumber = ADC_OFFSET_NONE;
  sConfig.Offset = 0;
  if (HAL_ADC_ConfigChannel(&hadc5, &sConfig) != HAL_OK)
  {
    Error_Handler();
  }

  /** Configure Regular Channel
  */
  sConfig.Channel = ADC_CHANNEL_TEMPSENSOR_ADC5;
  sConfig.Rank = ADC_REGULAR_RANK_2;
  if (HAL_ADC_ConfigChannel(&hadc5, &sConfig) != HAL_OK)
  {
    Error_Handler();
  }

  /** Configure Regular Channel
  */
  sConfig.Channel = ADC_CHANNEL_VBAT;
  sConfig.Rank = ADC_REGULAR_RANK_3;
  if (HAL_ADC_ConfigChannel(&hadc5, &sConfig) != HAL_OK)
  {
    Error_Handler();
  }

  /** Configure Regular Channel
  */
  sConfig.Channel = ADC_CHANNEL_VREFINT;
  sConfig.Rank = ADC_REGULAR_RANK_4;
  if (HAL_ADC_ConfigChannel(&hadc5, &sConfig) != HAL_OK)
  {
    Error_Handler();
  }

  /** Configure Regular Channel
  */
  sConfig.Channel = ADC_CHANNEL_VOPAMP5;
  sConfig.Rank = ADC_REGULAR_RANK_5;
  if (HAL_ADC_ConfigChannel(&hadc5, &sConfig) != HAL_OK)
  {
    Error_Handler();
  }

}

static void MX_COMP2_Init(void)
{

  hcomp2.Instance = COMP2;
  hcomp2.Init.InputPlus = COMP_INPUT_PLUS_IO1;
  hcomp2.Init.InputMinus = COMP_INPUT_MINUS_DAC1_CH2;
  hcomp2.Init.OutputPol = COMP_OUTPUTPOL_NONINVERTED;
  hcomp2.Init.Hysteresis = COMP_HYSTERESIS_NONE;
  hcomp2.Init.BlankingSrce = COMP_BLANKINGSRC_NONE;
  hcomp2.Init.TriggerMode = COMP_TRIGGERMODE_NONE;
  if (HAL_COMP_Init(&hcomp2) != HAL_OK)
  {
    Error_Handler();
  }

}

static void MX_COMP5_Init(void)
{

  hcomp5.Instance = COMP5;
  hcomp5.Init.InputPlus = COMP_INPUT_PLUS_IO1;
  hcomp5.Init.InputMinus = COMP_INPUT_MINUS_DAC1_CH2;
  hcomp5.Init.OutputPol = COMP_OUTPUTPOL_NONINVERTED;
  hcomp5.Init.Hysteresis = COMP_HYSTERESIS_NONE;
  hcomp5.Init.BlankingSrce = COMP_BLANKINGSRC_NONE;
  hcomp5.Init.TriggerMode = COMP_TRIGGERMODE_NONE;
  if (HAL_COMP_Init(&hcomp5) != HAL_OK)
  {
    Error_Handler();
  }

}

static void MX_CRC_Init(void)
{

  hcrc.Instance = CRC;
  hcrc.Init.DefaultPolynomialUse = DEFAULT_POLYNOMIAL_ENABLE;
  hcrc.Init.DefaultInitValueUse = DEFAULT_INIT_VALUE_ENABLE;
  hcrc.Init.InputDataInversionMode = CRC_INPUTDATA_INVERSION_NONE;
  hcrc.Init.OutputDataInversionMode = CRC_OUTPUTDATA_INVERSION_DISABLE;
  hcrc.InputDataFormat = CRC_INPUTDATA_FORMAT_BYTES;
  if (HAL_CRC_Init(&hcrc) != HAL_OK)
  {
    Error_Handler();
  }

}

static void MX_DAC1_Init(void)
{

  DAC_ChannelConfTypeDef sConfig = {0};

  /** DAC Initialization
  */
  hdac1.Instance = DAC1;
  if (HAL_DAC_Init(&hdac1) != HAL_OK)
  {
    Error_Handler();
  }

  /** DAC channel OUT1 config
  */
  sConfig.DAC_HighFrequency = DAC_HIGH_FREQUENCY_INTERFACE_MODE_AUTOMATIC;
  sConfig.DAC_DMADoubleDataMode = DISABLE;
  sConfig.DAC_SignedFormat = DISABLE;
  sConfig.DAC_SampleAndHold = DAC_SAMPLEANDHOLD_DISABLE;
  sConfig.DAC_Trigger = DAC_TRIGGER_SOFTWARE;
  sConfig.DAC_Trigger2 = DAC_TRIGGER_NONE;
  sConfig.DAC_OutputBuffer = DAC_OUTPUTBUFFER_ENABLE;
  sConfig.DAC_ConnectOnChipPeripheral = DAC_CHIPCONNECT_BOTH;
  sConfig.DAC_UserTrimming = DAC_TRIMMING_FACTORY;
  if (HAL_DAC_ConfigChannel(&hdac1, &sConfig, DAC_CHANNEL_1) != HAL_OK)
  {
    Error_Handler();
  }

  /** DAC channel OUT2 config
  */
  sConfig.DAC_Trigger = DAC_TRIGGER_NONE;
  sConfig.DAC_OutputBuffer = DAC_OUTPUTBUFFER_DISABLE;
  sConfig.DAC_ConnectOnChipPeripheral = DAC_CHIPCONNECT_INTERNAL;
  if (HAL_DAC_ConfigChannel(&hdac1, &sConfig, DAC_CHANNEL_2) != HAL_OK)
  {
    Error_Handler();
  }

}

static void MX_DAC2_Init(void)
{

  DAC_ChannelConfTypeDef sConfig = {0};

  /** DAC Initialization
  */
  hdac2.Instance = DAC2;
  if (HAL_DAC_Init(&hdac2) != HAL_OK)
  {
    Error_Handler();
  }

  /** DAC channel OUT1 config
  */
  sConfig.DAC_HighFrequency = DAC_HIGH_FREQUENCY_INTERFACE_MODE_AUTOMATIC;
  sConfig.DAC_DMADoubleDataMode = DISABLE;
  sConfig.DAC_SignedFormat = DISABLE;
  sConfig.DAC_SampleAndHold = DAC_SAMPLEANDHOLD_DISABLE;
  sConfig.DAC_Trigger = DAC_TRIGGER_SOFTWARE;
  sConfig.DAC_Trigger2 = DAC_TRIGGER_NONE;
  sConfig.DAC_OutputBuffer = DAC_OUTPUTBUFFER_ENABLE;
  sConfig.DAC_ConnectOnChipPeripheral = DAC_CHIPCONNECT_BOTH;
  sConfig.DAC_UserTrimming = DAC_TRIMMING_FACTORY;
  if (HAL_DAC_ConfigChannel(&hdac2, &sConfig, DAC_CHANNEL_1) != HAL_OK)
  {
    Error_Handler();
  }

}

static void MX_DAC4_Init(void)
{

  DAC_ChannelConfTypeDef sConfig = {0};

  /** DAC Initialization
  */
  hdac4.Instance = DAC4;
  if (HAL_DAC_Init(&hdac4) != HAL_OK)
  {
    Error_Handler();
  }

  /** DAC channel OUT1 config
  */
  sConfig.DAC_HighFrequency = DAC_HIGH_FREQUENCY_INTERFACE_MODE_AUTOMATIC;
  sConfig.DAC_DMADoubleDataMode = DISABLE;
  sConfig.DAC_SignedFormat = DISABLE;
  sConfig.DAC_SampleAndHold = DAC_SAMPLEANDHOLD_DISABLE;
  sConfig.DAC_Trigger = DAC_TRIGGER_SOFTWARE;
  sConfig.DAC_Trigger2 = DAC_TRIGGER_NONE;
  sConfig.DAC_OutputBuffer = DAC_OUTPUTBUFFER_DISABLE;
  sConfig.DAC_ConnectOnChipPeripheral = DAC_CHIPCONNECT_INTERNAL;
  sConfig.DAC_UserTrimming = DAC_TRIMMING_FACTORY;
  if (HAL_DAC_ConfigChannel(&hdac4, &sConfig, DAC_CHANNEL_1) != HAL_OK)
  {
    Error_Handler();
  }

}

static void MX_HRTIM1_Init(void)
{

  HRTIM_TimeBaseCfgTypeDef pTimeBaseCfg = {0};
  HRTIM_TimerCtlTypeDef pTimerCtl = {0};
  HRTIM_TimerCfgTypeDef pTimerCfg = {0};
  HRTIM_CompareCfgTypeDef pCompareCfg = {0};
  HRTIM_OutputCfgTypeDef pOutputCfg = {0};

  hhrtim1.Instance = HRTIM1;
  hhrtim1.Init.HRTIMInterruptResquests = HRTIM_IT_NONE;
  hhrtim1.Init.SyncOptions = HRTIM_SYNCOPTION_NONE;
  if (HAL_HRTIM_Init(&hhrtim1) != HAL_OK)
  {
    Error_Handler();
  }
  if (HAL_HRTIM_DLLCalibrationStart(&hhrtim1, HRTIM_CALIBRATIONRATE_3) != HAL_OK)
  {
    Error_Handler();
  }
  if (HAL_HRTIM_PollForDLLCalibration(&hhrtim1, 10) != HAL_OK)
  {
    Error_Handler();
  }
  pTimeBaseCfg.Period = 96;
  pTimeBaseCfg.RepetitionCounter = 0x00;
  pTimeBaseCfg.PrescalerRatio = HRTIM_PRESCALERRATIO_MUL32;
  pTimeBaseCfg.Mode = HRTIM_MODE_CONTINUOUS;
  if (HAL_HRTIM_TimeBaseConfig(&hhrtim1, HRTIM_TIMERINDEX_TIMER_C, &pTimeBaseCfg) != HAL_OK)
  {
    Error_Handler();
  }
  pTimerCtl.UpDownMode = HRTIM_TIMERUPDOWNMODE_UP;
  pTimerCtl.GreaterCMP1 = HRTIM_TIMERGTCMP1_EQUAL;
  pTimerCtl.DualChannelDacEnable = HRTIM_TIMER_DCDE_DISABLED;
  if (HAL_HRTIM_WaveformTimerControl(&hhrtim1, HRTIM_TIMERINDEX_TIMER_C, &pTimerCtl) != HAL_OK)
  {
    Error_Handler();
  }
  pTimerCfg.InterruptRequests = HRTIM_TIM_IT_NONE;
  pTimerCfg.DMARequests = HRTIM_TIM_DMA_NONE;
  pTimerCfg.DMASrcAddress = 0x0000;
  pTimerCfg.DMADstAddress = 0x0000;
  pTimerCfg.DMASize = 0x1;
  pTimerCfg.HalfModeEnable = HRTIM_HALFMODE_DISABLED;
  pTimerCfg.InterleavedMode = HRTIM_INTERLEAVED_MODE_DISABLED;
  pTimerCfg.StartOnSync = HRTIM_SYNCSTART_DISABLED;
  pTimerCfg.ResetOnSync = HRTIM_SYNCRESET_DISABLED;
  pTimerCfg.DACSynchro = HRTIM_DACSYNC_NONE;
  pTimerCfg.PreloadEnable = HRTIM_PRELOAD_DISABLED;
  pTimerCfg.UpdateGating = HRTIM_UPDATEGATING_INDEPENDENT;
  pTimerCfg.BurstMode = HRTIM_TIMERBURSTMODE_MAINTAINCLOCK;
  pTimerCfg.RepetitionUpdate = HRTIM_UPDATEONREPETITION_DISABLED;
  pTimerCfg.PushPull = HRTIM_TIMPUSHPULLMODE_DISABLED;
  pTimerCfg.FaultEnable = HRTIM_TIMFAULTENABLE_NONE;
  pTimerCfg.FaultLock = HRTIM_TIMFAULTLOCK_READWRITE;
  pTimerCfg.DeadTimeInsertion = HRTIM_TIMDEADTIMEINSERTION_DISABLED;
  pTimerCfg.DelayedProtectionMode = HRTIM_TIMER_A_B_C_DELAYEDPROTECTION_DISABLED;
  pTimerCfg.UpdateTrigger = HRTIM_TIMUPDATETRIGGER_NONE;
  pTimerCfg.ResetTrigger = HRTIM_TIMRESETTRIGGER_NONE;
  pTimerCfg.ResetUpdate = HRTIM_TIMUPDATEONRESET_DISABLED;
  pTimerCfg.ReSyncUpdate = HRTIM_TIMERESYNC_UPDATE_UNCONDITIONAL;
  if (HAL_HRTIM_WaveformTimerConfig(&hhrtim1, HRTIM_TIMERINDEX_TIMER_C, &pTimerCfg) != HAL_OK)
  {
    Error_Handler();
  }
  pCompareCfg.CompareValue = 48;
  if (HAL_HRTIM_WaveformCompareConfig(&hhrtim1, HRTIM_TIMERINDEX_TIMER_C, HRTIM_COMPAREUNIT_1, &pCompareCfg) != HAL_OK)
  {
    Error_Handler();
  }
  pOutputCfg.Polarity = HRTIM_OUTPUTPOLARITY_HIGH;
  pOutputCfg.SetSource = HRTIM_OUTPUTSET_TIMPER;
  pOutputCfg.ResetSource = HRTIM_OUTPUTRESET_TIMCMP1;
  pOutputCfg.IdleMode = HRTIM_OUTPUTIDLEMODE_NONE;
  pOutputCfg.IdleLevel = HRTIM_OUTPUTIDLELEVEL_INACTIVE;
  pOutputCfg.FaultLevel = HRTIM_OUTPUTFAULTLEVEL_NONE;
  pOutputCfg.ChopperModeEnable = HRTIM_OUTPUTCHOPPERMODE_DISABLED;
  pOutputCfg.BurstModeEntryDelayed = HRTIM_OUTPUTBURSTMODEENTRY_REGULAR;
  if (HAL_HRTIM_WaveformOutputConfig(&hhrtim1, HRTIM_TIMERINDEX_TIMER_C, HRTIM_OUTPUT_TC1, &pOutputCfg) != HAL_OK)
  {
    Error_Handler();
  }
  HAL_HRTIM_MspPostInit(&hhrtim1);

}

static void MX_I2C3_Init(void)
{

  hi2c3.Instance = I2C3;
  hi2c3.Init.Timing = 0x10E32879;
  hi2c3.Init.OwnAddress1 = 0;
  hi2c3.Init.AddressingMode = I2C_ADDRESSINGMODE_7BIT;
  hi2c3.Init.DualAddressMode = I2C_DUALADDRESS_DISABLE;
  hi2c3.Init.OwnAddress2 = 0;
  hi2c3.Init.OwnAddress2Masks = I2C_OA2_NOMASK;
  hi2c3.Init.GeneralCallMode = I2C_GENERALCALL_DISABLE;
  hi2c3.Init.NoStretchMode = I2C_NOSTRETCH_DISABLE;
  if (HAL_I2C_Init(&hi2c3) != HAL_OK)
  {
    Error_Handler();
  }

  /** Configure Analogue filter
  */
  if (HAL_I2CEx_ConfigAnalogFilter(&hi2c3, I2C_ANALOGFILTER_ENABLE) != HAL_OK)
  {
    Error_Handler();
  }

  /** Configure Digital filter
  */
  if (HAL_I2CEx_ConfigDigitalFilter(&hi2c3, 0) != HAL_OK)
  {
    Error_Handler();
  }

}

static void MX_LPUART1_UART_Init(void)
{

  hlpuart1.Instance = LPUART1;
  hlpuart1.Init.BaudRate = 921600;
  hlpuart1.Init.WordLength = UART_WORDLENGTH_8B;
  hlpuart1.Init.StopBits = UART_STOPBITS_1;
  hlpuart1.Init.Parity = UART_PARITY_NONE;
  hlpuart1.Init.Mode = UART_MODE_TX_RX;
  hlpuart1.Init.HwFlowCtl = UART_HWCONTROL_NONE;
  hlpuart1.Init.OneBitSampling = UART_ONE_BIT_SAMPLE_DISABLE;
  hlpuart1.Init.ClockPrescaler = UART_PRESCALER_DIV1;
  hlpuart1.AdvancedInit.AdvFeatureInit = UART_ADVFEATURE_NO_INIT;
  if (HAL_UART_Init(&hlpuart1) != HAL_OK)
  {
    Error_Handler();
  }
  if (HAL_UARTEx_SetTxFifoThreshold(&hlpuart1, UART_TXFIFO_THRESHOLD_1_8) != HAL_OK)
  {
    Error_Handler();
  }
  if (HAL_UARTEx_SetRxFifoThreshold(&hlpuart1, UART_RXFIFO_THRESHOLD_1_8) != HAL_OK)
  {
    Error_Handler();
  }
  if (HAL_UARTEx_DisableFifoMode(&hlpuart1) != HAL_OK)
  {
    Error_Handler();
  }

}

static void MX_OPAMP1_Init(void)
{

  hopamp1.Instance = OPAMP1;
  hopamp1.Init.PowerMode = OPAMP_POWERMODE_NORMALSPEED;
  hopamp1.Init.Mode = OPAMP_PGA_MODE;
  hopamp1.Init.NonInvertingInput = OPAMP_NONINVERTINGINPUT_IO2;
  hopamp1.Init.InternalOutput = ENABLE;
  hopamp1.Init.TimerControlledMuxmode = OPAMP_TIMERCONTROLLEDMUXMODE_DISABLE;
  hopamp1.Init.PgaConnect = OPAMP_PGA_CONNECT_INVERTINGINPUT_NO;
  hopamp1.Init.PgaGain = OPAMP_PGA_GAIN_2_OR_MINUS_1;
  hopamp1.Init.UserTrimming = OPAMP_TRIMMING_FACTORY;
  if (HAL_OPAMP_Init(&hopamp1) != HAL_OK)
  {
    Error_Handler();
  }

}

static void MX_OPAMP2_Init(void)
{

  hopamp2.Instance = OPAMP2;
  hopamp2.Init.PowerMode = OPAMP_POWERMODE_NORMALSPEED;
  hopamp2.Init.Mode = OPAMP_FOLLOWER_MODE;
  hopamp2.Init.NonInvertingInput = OPAMP_NONINVERTINGINPUT_IO0;
  hopamp2.Init.InternalOutput = ENABLE;
  hopamp2.Init.TimerControlledMuxmode = OPAMP_TIMERCONTROLLEDMUXMODE_DISABLE;
  hopamp2.Init.UserTrimming = OPAMP_TRIMMING_FACTORY;
  if (HAL_OPAMP_Init(&hopamp2) != HAL_OK)
  {
    Error_Handler();
  }

}

static void MX_OPAMP3_Init(void)
{

  hopamp3.Instance = OPAMP3;
  hopamp3.Init.PowerMode = OPAMP_POWERMODE_NORMALSPEED;
  hopamp3.Init.Mode = OPAMP_FOLLOWER_MODE;
  hopamp3.Init.NonInvertingInput = OPAMP_NONINVERTINGINPUT_IO1;
  hopamp3.Init.InternalOutput = ENABLE;
  hopamp3.Init.TimerControlledMuxmode = OPAMP_TIMERCONTROLLEDMUXMODE_DISABLE;
  hopamp3.Init.UserTrimming = OPAMP_TRIMMING_FACTORY;
  if (HAL_OPAMP_Init(&hopamp3) != HAL_OK)
  {
    Error_Handler();
  }

}

static void MX_OPAMP5_Init(void)
{

  hopamp5.Instance = OPAMP5;
  hopamp5.Init.PowerMode = OPAMP_POWERMODE_NORMALSPEED;
  hopamp5.Init.Mode = OPAMP_FOLLOWER_MODE;
  hopamp5.Init.NonInvertingInput = OPAMP_NONINVERTINGINPUT_IO2;
  hopamp5.Init.InternalOutput = ENABLE;
  hopamp5.Init.TimerControlledMuxmode = OPAMP_TIMERCONTROLLEDMUXMODE_DISABLE;
  hopamp5.Init.UserTrimming = OPAMP_TRIMMING_FACTORY;
  if (HAL_OPAMP_Init(&hopamp5) != HAL_OK)
  {
    Error_Handler();
  }

}

static void MX_OPAMP6_Init(void)
{

  hopamp6.Instance = OPAMP6;
  hopamp6.Init.PowerMode = OPAMP_POWERMODE_NORMALSPEED;
  hopamp6.Init.Mode = OPAMP_PGA_MODE;
  hopamp6.Init.NonInvertingInput = OPAMP_NONINVERTINGINPUT_IO2;
  hopamp6.Init.InternalOutput = ENABLE;
  hopamp6.Init.TimerControlledMuxmode = OPAMP_TIMERCONTROLLEDMUXMODE_DISABLE;
  hopamp6.Init.PgaConnect = OPAMP_PGA_CONNECT_INVERTINGINPUT_NO;
  hopamp6.Init.PgaGain = OPAMP_PGA_GAIN_2_OR_MINUS_1;
  hopamp6.Init.UserTrimming = OPAMP_TRIMMING_FACTORY;
  if (HAL_OPAMP_Init(&hopamp6) != HAL_OK)
  {
    Error_Handler();
  }

}

static void MX_SPI3_Init(void)
{

  /* SPI3 parameter configuration*/
  hspi3.Instance = SPI3;
  hspi3.Init.Mode = SPI_MODE_MASTER;
  hspi3.Init.Direction = SPI_DIRECTION_1LINE;
  hspi3.Init.DataSize = SPI_DATASIZE_8BIT;
  hspi3.Init.CLKPolarity = SPI_POLARITY_HIGH;
  hspi3.Init.CLKPhase = SPI_PHASE_1EDGE;
  hspi3.Init.NSS = SPI_NSS_SOFT;
  hspi3.Init.BaudRatePrescaler = SPI_BAUDRATEPRESCALER_8;
  hspi3.Init.FirstBit = SPI_FIRSTBIT_MSB;
  hspi3.Init.TIMode = SPI_TIMODE_DISABLE;
  hspi3.Init.CRCCalculation = SPI_CRCCALCULATION_DISABLE;
  hspi3.Init.CRCPolynomial = 7;
  hspi3.Init.CRCLength = SPI_CRC_LENGTH_DATASIZE;
  hspi3.Init.NSSPMode = SPI_NSS_PULSE_ENABLE;
  if (HAL_SPI_Init(&hspi3) != HAL_OK)
  {
    Error_Handler();
  }

}

static void MX_TIM1_Init(void)
{

  TIM_Encoder_InitTypeDef sConfig = {0};
  TIM_MasterConfigTypeDef sMasterConfig = {0};

  htim1.Instance = TIM1;
  htim1.Init.Prescaler = 0;
  htim1.Init.CounterMode = TIM_COUNTERMODE_UP;
  htim1.Init.Period = 65535;
  htim1.Init.ClockDivision = TIM_CLOCKDIVISION_DIV1;
  htim1.Init.RepetitionCounter = 0;
  htim1.Init.AutoReloadPreload = TIM_AUTORELOAD_PRELOAD_DISABLE;
  sConfig.EncoderMode = TIM_ENCODERMODE_TI1;
  sConfig.IC1Polarity = TIM_ICPOLARITY_RISING;
  sConfig.IC1Selection = TIM_ICSELECTION_DIRECTTI;
  sConfig.IC1Prescaler = TIM_ICPSC_DIV1;
  sConfig.IC1Filter = 15;
  sConfig.IC2Polarity = TIM_ICPOLARITY_RISING;
  sConfig.IC2Selection = TIM_ICSELECTION_DIRECTTI;
  sConfig.IC2Prescaler = TIM_ICPSC_DIV1;
  sConfig.IC2Filter = 15;
  if (HAL_TIM_Encoder_Init(&htim1, &sConfig) != HAL_OK)
  {
    Error_Handler();
  }
  sMasterConfig.MasterOutputTrigger = TIM_TRGO_RESET;
  sMasterConfig.MasterOutputTrigger2 = TIM_TRGO2_RESET;
  sMasterConfig.MasterSlaveMode = TIM_MASTERSLAVEMODE_DISABLE;
  if (HAL_TIMEx_MasterConfigSynchronization(&htim1, &sMasterConfig) != HAL_OK)
  {
    Error_Handler();
  }

}

static void MX_TIM3_Init(void)
{

  TIM_Encoder_InitTypeDef sConfig = {0};
  TIM_MasterConfigTypeDef sMasterConfig = {0};

  htim3.Instance = TIM3;
  htim3.Init.Prescaler = 0;
  htim3.Init.CounterMode = TIM_COUNTERMODE_UP;
  htim3.Init.Period = 65535;
  htim3.Init.ClockDivision = TIM_CLOCKDIVISION_DIV1;
  htim3.Init.AutoReloadPreload = TIM_AUTORELOAD_PRELOAD_DISABLE;
  sConfig.EncoderMode = TIM_ENCODERMODE_TI1;
  sConfig.IC1Polarity = TIM_ICPOLARITY_RISING;
  sConfig.IC1Selection = TIM_ICSELECTION_DIRECTTI;
  sConfig.IC1Prescaler = TIM_ICPSC_DIV1;
  sConfig.IC1Filter = 15;
  sConfig.IC2Polarity = TIM_ICPOLARITY_RISING;
  sConfig.IC2Selection = TIM_ICSELECTION_DIRECTTI;
  sConfig.IC2Prescaler = TIM_ICPSC_DIV1;
  sConfig.IC2Filter = 15;
  if (HAL_TIM_Encoder_Init(&htim3, &sConfig) != HAL_OK)
  {
    Error_Handler();
  }
  sMasterConfig.MasterOutputTrigger = TIM_TRGO_RESET;
  sMasterConfig.MasterSlaveMode = TIM_MASTERSLAVEMODE_DISABLE;
  if (HAL_TIMEx_MasterConfigSynchronization(&htim3, &sMasterConfig) != HAL_OK)
  {
    Error_Handler();
  }

}

static void MX_TIM4_Init(void)
{

  TIM_Encoder_InitTypeDef sConfig = {0};
  TIM_MasterConfigTypeDef sMasterConfig = {0};

  htim4.Instance = TIM4;
  htim4.Init.Prescaler = 0;
  htim4.Init.CounterMode = TIM_COUNTERMODE_UP;
  htim4.Init.Period = 65535;
  htim4.Init.ClockDivision = TIM_CLOCKDIVISION_DIV1;
  htim4.Init.AutoReloadPreload = TIM_AUTORELOAD_PRELOAD_DISABLE;
  sConfig.EncoderMode = TIM_ENCODERMODE_TI1;
  sConfig.IC1Polarity = TIM_ICPOLARITY_RISING;
  sConfig.IC1Selection = TIM_ICSELECTION_DIRECTTI;
  sConfig.IC1Prescaler = TIM_ICPSC_DIV1;
  sConfig.IC1Filter = 15;
  sConfig.IC2Polarity = TIM_ICPOLARITY_RISING;
  sConfig.IC2Selection = TIM_ICSELECTION_DIRECTTI;
  sConfig.IC2Prescaler = TIM_ICPSC_DIV1;
  sConfig.IC2Filter = 15;
  if (HAL_TIM_Encoder_Init(&htim4, &sConfig) != HAL_OK)
  {
    Error_Handler();
  }
  sMasterConfig.MasterOutputTrigger = TIM_TRGO_RESET;
  sMasterConfig.MasterSlaveMode = TIM_MASTERSLAVEMODE_DISABLE;
  if (HAL_TIMEx_MasterConfigSynchronization(&htim4, &sMasterConfig) != HAL_OK)
  {
    Error_Handler();
  }

}

static void MX_TIM6_Init(void)
{

  TIM_MasterConfigTypeDef sMasterConfig = {0};

  htim6.Instance = TIM6;
  htim6.Init.Prescaler = 0;
  htim6.Init.CounterMode = TIM_COUNTERMODE_UP;
  htim6.Init.Period = 44;
  htim6.Init.AutoReloadPreload = TIM_AUTORELOAD_PRELOAD_DISABLE;
  if (HAL_TIM_Base_Init(&htim6) != HAL_OK)
  {
    Error_Handler();
  }
  sMasterConfig.MasterOutputTrigger = TIM_TRGO_UPDATE;
  sMasterConfig.MasterSlaveMode = TIM_MASTERSLAVEMODE_DISABLE;
  if (HAL_TIMEx_MasterConfigSynchronization(&htim6, &sMasterConfig) != HAL_OK)
  {
    Error_Handler();
  }

}

static void MX_TIM7_Init(void)
{

  TIM_MasterConfigTypeDef sMasterConfig = {0};

  htim7.Instance = TIM7;
  htim7.Init.Prescaler = 180-1;
  htim7.Init.CounterMode = TIM_COUNTERMODE_UP;
  htim7.Init.Period = 1000-1;
  htim7.Init.AutoReloadPreload = TIM_AUTORELOAD_PRELOAD_DISABLE;
  if (HAL_TIM_Base_Init(&htim7) != HAL_OK)
  {
    Error_Handler();
  }
  sMasterConfig.MasterOutputTrigger = TIM_TRGO_UPDATE;
  sMasterConfig.MasterSlaveMode = TIM_MASTERSLAVEMODE_DISABLE;
  if (HAL_TIMEx_MasterConfigSynchronization(&htim7, &sMasterConfig) != HAL_OK)
  {
    Error_Handler();
  }

}

static void MX_TIM8_Init(void)
{

  TIM_ClockConfigTypeDef sClockSourceConfig = {0};
  TIM_MasterConfigTypeDef sMasterConfig = {0};
  TIM_OC_InitTypeDef sConfigOC = {0};
  TIM_BreakDeadTimeConfigTypeDef sBreakDeadTimeConfig = {0};

  htim8.Instance = TIM8;
  htim8.Init.Prescaler = 0;
  htim8.Init.CounterMode = TIM_COUNTERMODE_UP;
  htim8.Init.Period = 179;
  htim8.Init.ClockDivision = TIM_CLOCKDIVISION_DIV1;
  htim8.Init.RepetitionCounter = 0;
  htim8.Init.AutoReloadPreload = TIM_AUTORELOAD_PRELOAD_DISABLE;
  if (HAL_TIM_Base_Init(&htim8) != HAL_OK)
  {
    Error_Handler();
  }
  sClockSourceConfig.ClockSource = TIM_CLOCKSOURCE_INTERNAL;
  if (HAL_TIM_ConfigClockSource(&htim8, &sClockSourceConfig) != HAL_OK)
  {
    Error_Handler();
  }
  if (HAL_TIM_PWM_Init(&htim8) != HAL_OK)
  {
    Error_Handler();
  }
  sMasterConfig.MasterOutputTrigger = TIM_TRGO_RESET;
  sMasterConfig.MasterOutputTrigger2 = TIM_TRGO2_RESET;
  sMasterConfig.MasterSlaveMode = TIM_MASTERSLAVEMODE_DISABLE;
  if (HAL_TIMEx_MasterConfigSynchronization(&htim8, &sMasterConfig) != HAL_OK)
  {
    Error_Handler();
  }
  sConfigOC.OCMode = TIM_OCMODE_PWM2;
  sConfigOC.Pulse = 90;
  sConfigOC.OCPolarity = TIM_OCPOLARITY_LOW;
  sConfigOC.OCNPolarity = TIM_OCNPOLARITY_HIGH;
  sConfigOC.OCFastMode = TIM_OCFAST_DISABLE;
  sConfigOC.OCIdleState = TIM_OCIDLESTATE_RESET;
  sConfigOC.OCNIdleState = TIM_OCNIDLESTATE_RESET;
  if (HAL_TIM_PWM_ConfigChannel(&htim8, &sConfigOC, TIM_CHANNEL_1) != HAL_OK)
  {
    Error_Handler();
  }
  sConfigOC.OCMode = TIM_OCMODE_PWM1;
  sConfigOC.OCPolarity = TIM_OCPOLARITY_HIGH;
  sConfigOC.OCIdleState = TIM_OCIDLESTATE_SET;
  if (HAL_TIM_PWM_ConfigChannel(&htim8, &sConfigOC, TIM_CHANNEL_3) != HAL_OK)
  {
    Error_Handler();
  }
  sBreakDeadTimeConfig.OffStateRunMode = TIM_OSSR_DISABLE;
  sBreakDeadTimeConfig.OffStateIDLEMode = TIM_OSSI_DISABLE;
  sBreakDeadTimeConfig.LockLevel = TIM_LOCKLEVEL_OFF;
  sBreakDeadTimeConfig.DeadTime = 0;
  sBreakDeadTimeConfig.BreakState = TIM_BREAK_DISABLE;
  sBreakDeadTimeConfig.BreakPolarity = TIM_BREAKPOLARITY_HIGH;
  sBreakDeadTimeConfig.BreakFilter = 0;
  sBreakDeadTimeConfig.BreakAFMode = TIM_BREAK_AFMODE_INPUT;
  sBreakDeadTimeConfig.Break2State = TIM_BREAK2_DISABLE;
  sBreakDeadTimeConfig.Break2Polarity = TIM_BREAK2POLARITY_HIGH;
  sBreakDeadTimeConfig.Break2Filter = 0;
  sBreakDeadTimeConfig.Break2AFMode = TIM_BREAK_AFMODE_INPUT;
  sBreakDeadTimeConfig.AutomaticOutput = TIM_AUTOMATICOUTPUT_DISABLE;
  if (HAL_TIMEx_ConfigBreakDeadTime(&htim8, &sBreakDeadTimeConfig) != HAL_OK)
  {
    Error_Handler();
  }
  HAL_TIM_MspPostInit(&htim8);

}

static void MX_TIM15_Init(void)
{

  TIM_ClockConfigTypeDef sClockSourceConfig = {0};
  TIM_MasterConfigTypeDef sMasterConfig = {0};
  TIM_OC_InitTypeDef sConfigOC = {0};
  TIM_BreakDeadTimeConfigTypeDef sBreakDeadTimeConfig = {0};

  htim15.Instance = TIM15;
  htim15.Init.Prescaler = 150;
  htim15.Init.CounterMode = TIM_COUNTERMODE_UP;
  htim15.Init.Period = 999;
  htim15.Init.ClockDivision = TIM_CLOCKDIVISION_DIV1;
  htim15.Init.RepetitionCounter = 0;
  htim15.Init.AutoReloadPreload = TIM_AUTORELOAD_PRELOAD_DISABLE;
  if (HAL_TIM_Base_Init(&htim15) != HAL_OK)
  {
    Error_Handler();
  }
  sClockSourceConfig.ClockSource = TIM_CLOCKSOURCE_INTERNAL;
  if (HAL_TIM_ConfigClockSource(&htim15, &sClockSourceConfig) != HAL_OK)
  {
    Error_Handler();
  }
  if (HAL_TIM_PWM_Init(&htim15) != HAL_OK)
  {
    Error_Handler();
  }
  sMasterConfig.MasterOutputTrigger = TIM_TRGO_RESET;
  sMasterConfig.MasterSlaveMode = TIM_MASTERSLAVEMODE_DISABLE;
  if (HAL_TIMEx_MasterConfigSynchronization(&htim15, &sMasterConfig) != HAL_OK)
  {
    Error_Handler();
  }
  sConfigOC.OCMode = TIM_OCMODE_PWM1;
  sConfigOC.Pulse = 499;
  sConfigOC.OCPolarity = TIM_OCPOLARITY_HIGH;
  sConfigOC.OCNPolarity = TIM_OCNPOLARITY_HIGH;
  sConfigOC.OCFastMode = TIM_OCFAST_DISABLE;
  sConfigOC.OCIdleState = TIM_OCIDLESTATE_RESET;
  sConfigOC.OCNIdleState = TIM_OCNIDLESTATE_RESET;
  if (HAL_TIM_PWM_ConfigChannel(&htim15, &sConfigOC, TIM_CHANNEL_1) != HAL_OK)
  {
    Error_Handler();
  }
  sBreakDeadTimeConfig.OffStateRunMode = TIM_OSSR_DISABLE;
  sBreakDeadTimeConfig.OffStateIDLEMode = TIM_OSSI_DISABLE;
  sBreakDeadTimeConfig.LockLevel = TIM_LOCKLEVEL_OFF;
  sBreakDeadTimeConfig.DeadTime = 0;
  sBreakDeadTimeConfig.BreakState = TIM_BREAK_DISABLE;
  sBreakDeadTimeConfig.BreakPolarity = TIM_BREAKPOLARITY_HIGH;
  sBreakDeadTimeConfig.BreakFilter = 0;
  sBreakDeadTimeConfig.AutomaticOutput = TIM_AUTOMATICOUTPUT_DISABLE;
  if (HAL_TIMEx_ConfigBreakDeadTime(&htim15, &sBreakDeadTimeConfig) != HAL_OK)
  {
    Error_Handler();
  }
  HAL_TIM_MspPostInit(&htim15);

}

static void MX_TIM20_Init(void)
{

  TIM_Encoder_InitTypeDef sConfig = {0};
  TIM_MasterConfigTypeDef sMasterConfig = {0};

  htim20.Instance = TIM20;
  htim20.Init.Prescaler = 0;
  htim20.Init.CounterMode = TIM_COUNTERMODE_UP;
  htim20.Init.Period = 65535;
  htim20.Init.ClockDivision = TIM_CLOCKDIVISION_DIV1;
  htim20.Init.RepetitionCounter = 0;
  htim20.Init.AutoReloadPreload = TIM_AUTORELOAD_PRELOAD_DISABLE;
  sConfig.EncoderMode = TIM_ENCODERMODE_TI1;
  sConfig.IC1Polarity = TIM_ICPOLARITY_RISING;
  sConfig.IC1Selection = TIM_ICSELECTION_DIRECTTI;
  sConfig.IC1Prescaler = TIM_ICPSC_DIV1;
  sConfig.IC1Filter = 15;
  sConfig.IC2Polarity = TIM_ICPOLARITY_RISING;
  sConfig.IC2Selection = TIM_ICSELECTION_DIRECTTI;
  sConfig.IC2Prescaler = TIM_ICPSC_DIV1;
  sConfig.IC2Filter = 15;
  if (HAL_TIM_Encoder_Init(&htim20, &sConfig) != HAL_OK)
  {
    Error_Handler();
  }
  sMasterConfig.MasterOutputTrigger = TIM_TRGO_RESET;
  sMasterConfig.MasterOutputTrigger2 = TIM_TRGO2_RESET;
  sMasterConfig.MasterSlaveMode = TIM_MASTERSLAVEMODE_DISABLE;
  if (HAL_TIMEx_MasterConfigSynchronization(&htim20, &sMasterConfig) != HAL_OK)
  {
    Error_Handler();
  }

}

static void MX_DMA_Init(void)
{

  /* DMA controller clock enable */
  __HAL_RCC_DMAMUX1_CLK_ENABLE();
  __HAL_RCC_DMA1_CLK_ENABLE();

  /* DMA interrupt init */
  /* DMA1_Channel1_IRQn interrupt configuration */
  HAL_NVIC_SetPriority(DMA1_Channel1_IRQn, 0, 0);
  HAL_NVIC_EnableIRQ(DMA1_Channel1_IRQn);
  /* DMA1_Channel2_IRQn interrupt configuration */
  HAL_NVIC_SetPriority(DMA1_Channel2_IRQn, 0, 0);
  HAL_NVIC_EnableIRQ(DMA1_Channel2_IRQn);
  /* DMA1_Channel3_IRQn interrupt configuration */
  HAL_NVIC_SetPriority(DMA1_Channel3_IRQn, 0, 0);
  HAL_NVIC_EnableIRQ(DMA1_Channel3_IRQn);
  /* DMA1_Channel4_IRQn interrupt configuration */
  HAL_NVIC_SetPriority(DMA1_Channel4_IRQn, 0, 0);
  HAL_NVIC_EnableIRQ(DMA1_Channel4_IRQn);
  /* DMA1_Channel5_IRQn interrupt configuration */
  HAL_NVIC_SetPriority(DMA1_Channel5_IRQn, 0, 0);
  HAL_NVIC_EnableIRQ(DMA1_Channel5_IRQn);
  /* DMA1_Channel6_IRQn interrupt configuration */
  HAL_NVIC_SetPriority(DMA1_Channel6_IRQn, 0, 0);
  HAL_NVIC_EnableIRQ(DMA1_Channel6_IRQn);

}

static void MX_GPIO_Init(void)
{
  GPIO_InitTypeDef GPIO_InitStruct = {0};

  /* GPIO Ports Clock Enable */
  __HAL_RCC_GPIOC_CLK_ENABLE();
  __HAL_RCC_GPIOF_CLK_ENABLE();
  __HAL_RCC_GPIOA_CLK_ENABLE();
  __HAL_RCC_GPIOB_CLK_ENABLE();
  __HAL_RCC_GPIOD_CLK_ENABLE();

  /*Configure GPIO pin Output Level */
  HAL_GPIO_WritePin(GPIOC, AC_DC_CH2_Pin|CD_CH2_A_Pin|CD_CH2_B_Pin|CD_CH1_A_Pin
                          |ST7789_DC_Pin, GPIO_PIN_RESET);

  /*Configure GPIO pin Output Level */
  HAL_GPIO_WritePin(GPIOA, CD_CH2_C_Pin|AC_DC_CH1_Pin|CD_CH1_C_Pin, GPIO_PIN_RESET);

  /*Configure GPIO pin Output Level */
  HAL_GPIO_WritePin(GPIOB, CD_CH1_B_Pin|TLC5952_SCLK_Pin|TLC5952_LAT_Pin|TLC5952_SIN_Pin, GPIO_PIN_RESET);

  /*Configure GPIO pin Output Level */
  HAL_GPIO_WritePin(FT6336_RST_GPIO_Port, FT6336_RST_Pin, GPIO_PIN_RESET);

  /*Configure GPIO pins : AC_DC_CH2_Pin CD_CH2_A_Pin CD_CH2_B_Pin CD_CH1_A_Pin
                           ST7789_DC_Pin */
  GPIO_InitStruct.Pin = AC_DC_CH2_Pin|CD_CH2_A_Pin|CD_CH2_B_Pin|CD_CH1_A_Pin
                          |ST7789_DC_Pin;
  GPIO_InitStruct.Mode = GPIO_MODE_OUTPUT_PP;
  GPIO_InitStruct.Pull = GPIO_NOPULL;
  GPIO_InitStruct.Speed = GPIO_SPEED_FREQ_LOW;
  HAL_GPIO_Init(GPIOC, &GPIO_InitStruct);

  /*Configure GPIO pin : PA0 */
  GPIO_InitStruct.Pin = GPIO_PIN_0;
  GPIO_InitStruct.Mode = GPIO_MODE_AF_PP;
  GPIO_InitStruct.Pull = GPIO_NOPULL;
  GPIO_InitStruct.Speed = GPIO_SPEED_FREQ_LOW;
  GPIO_InitStruct.Alternate = GPIO_AF14_TIM2;
  HAL_GPIO_Init(GPIOA, &GPIO_InitStruct);

  /*Configure GPIO pins : CD_CH2_C_Pin AC_DC_CH1_Pin CD_CH1_C_Pin */
  GPIO_InitStruct.Pin = CD_CH2_C_Pin|AC_DC_CH1_Pin|CD_CH1_C_Pin;
  GPIO_InitStruct.Mode = GPIO_MODE_OUTPUT_PP;
  GPIO_InitStruct.Pull = GPIO_NOPULL;
  GPIO_InitStruct.Speed = GPIO_SPEED_FREQ_LOW;
  HAL_GPIO_Init(GPIOA, &GPIO_InitStruct);

  /*Configure GPIO pins : PA2 PA3 PA10 */
  GPIO_InitStruct.Pin = GPIO_PIN_2|GPIO_PIN_3|GPIO_PIN_10;
  GPIO_InitStruct.Mode = GPIO_MODE_IT_RISING;
  GPIO_InitStruct.Pull = GPIO_NOPULL;
  HAL_GPIO_Init(GPIOA, &GPIO_InitStruct);

  /*Configure GPIO pin : PC4 */
  GPIO_InitStruct.Pin = GPIO_PIN_4;
  GPIO_InitStruct.Mode = GPIO_MODE_IT_RISING;
  GPIO_InitStruct.Pull = GPIO_NOPULL;
  HAL_GPIO_Init(GPIOC, &GPIO_InitStruct);

  /*Configure GPIO pins : PB0 PB1 PB8 */
  GPIO_InitStruct.Pin = GPIO_PIN_0|GPIO_PIN_1|GPIO_PIN_8;
  GPIO_InitStruct.Mode = GPIO_MODE_IT_RISING;
  GPIO_InitStruct.Pull = GPIO_NOPULL;
  HAL_GPIO_Init(GPIOB, &GPIO_InitStruct);

  /*Configure GPIO pins : CD_CH1_B_Pin TLC5952_SCLK_Pin TLC5952_LAT_Pin TLC5952_SIN_Pin */
  GPIO_InitStruct.Pin = CD_CH1_B_Pin|TLC5952_SCLK_Pin|TLC5952_LAT_Pin|TLC5952_SIN_Pin;
  GPIO_InitStruct.Mode = GPIO_MODE_OUTPUT_PP;
  GPIO_InitStruct.Pull = GPIO_NOPULL;
  GPIO_InitStruct.Speed = GPIO_SPEED_FREQ_LOW;
  HAL_GPIO_Init(GPIOB, &GPIO_InitStruct);

  /*Configure GPIO pin : FT6336_RST_Pin */
  GPIO_InitStruct.Pin = FT6336_RST_Pin;
  GPIO_InitStruct.Mode = GPIO_MODE_OUTPUT_PP;
  GPIO_InitStruct.Pull = GPIO_NOPULL;
  GPIO_InitStruct.Speed = GPIO_SPEED_FREQ_LOW;
  HAL_GPIO_Init(FT6336_RST_GPIO_Port, &GPIO_InitStruct);

  /* EXTI interrupt init*/
  HAL_NVIC_SetPriority(EXTI0_IRQn, 0, 0);
  HAL_NVIC_EnableIRQ(EXTI0_IRQn);

  HAL_NVIC_SetPriority(EXTI1_IRQn, 0, 0);
  HAL_NVIC_EnableIRQ(EXTI1_IRQn);

  HAL_NVIC_SetPriority(EXTI2_IRQn, 0, 0);
  HAL_NVIC_EnableIRQ(EXTI2_IRQn);

  HAL_NVIC_SetPriority(EXTI3_IRQn, 0, 0);
  HAL_NVIC_EnableIRQ(EXTI3_IRQn);

  HAL_NVIC_SetPriority(EXTI4_IRQn, 0, 0);
  HAL_NVIC_EnableIRQ(EXTI4_IRQn);

  HAL_NVIC_SetPriority(EXTI9_5_IRQn, 0, 0);
  HAL_NVIC_EnableIRQ(EXTI9_5_IRQn);

  HAL_NVIC_SetPriority(EXTI15_10_IRQn, 0, 0);
  HAL_NVIC_EnableIRQ(EXTI15_10_IRQn);

}

/* USER CODE BEGIN 4 */

void HAL_ADC_ConvHalfCpltCallback	(ADC_HandleTypeDef *hadc)
{
    if (!LOCK_CH1 ) {
        for (size_t i = 0; i < DPO_DEEP; i++) {
            BUFFER_DPO_CH1_PROC[i] = BUFFER_DPO_CH1[i];

            BUFFER_DPO_CH2_PROC[i] = BUFFER_DPO_CH2[i];
        }
        LOCK_CH1 =1;

    }
}

/* USER CODE END 4 */

void Error_Handler(void)
{
  __disable_irq();
  while (1)
  {
  }
}
